VERSION 5.7 ;
  NOWIREEXTENSIONATPIN ON ;
  DIVIDERCHAR "/" ;
  BUSBITCHARS "[]" ;
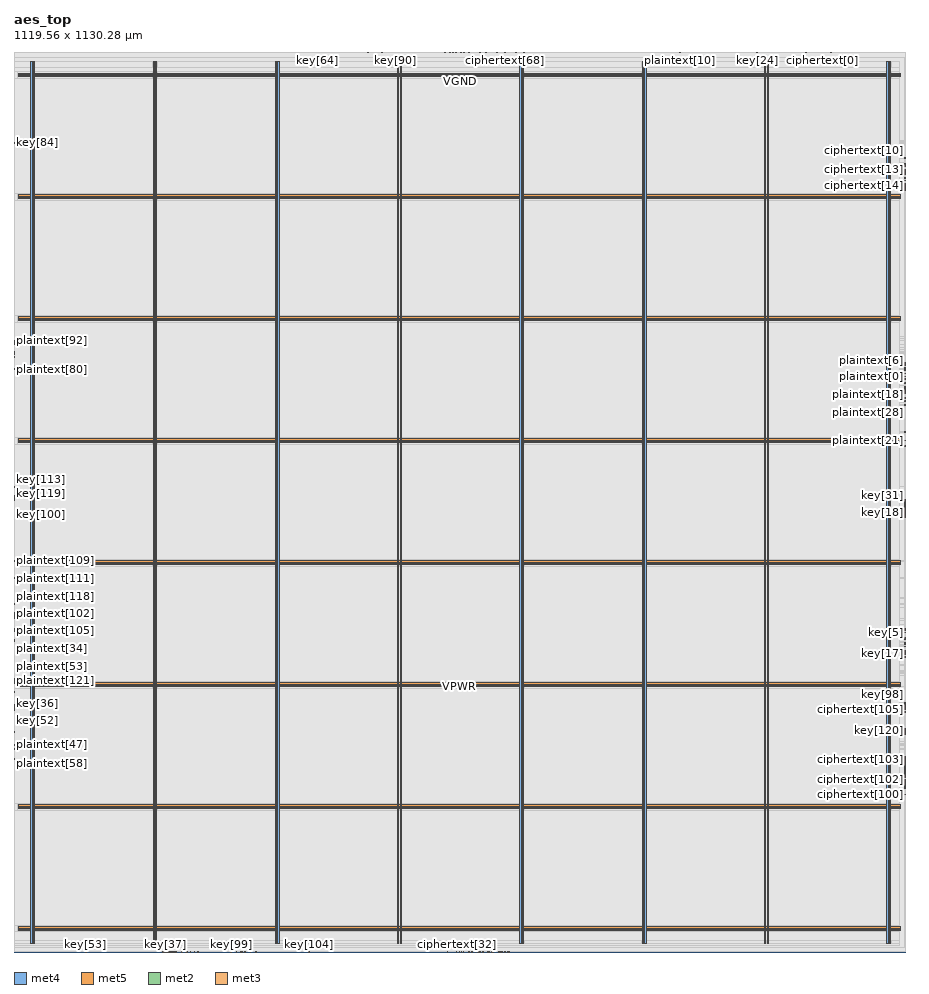
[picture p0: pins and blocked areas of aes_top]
MACRO aes_top
  CLASS BLOCK ;
  FOREIGN aes_top ;
  ORIGIN 0.000 0.000 ;
  SIZE 1119.560 BY 1130.280 ;
  PIN VGND
    DIRECTION INOUT ;
    USE GROUND ;
    PORT
      LAYER met4 ;
        RECT 24.340 10.640 25.940 1118.160 ;
    END
    PORT
      LAYER met4 ;
        RECT 177.940 10.640 179.540 1118.160 ;
    END
    PORT
      LAYER met4 ;
        RECT 331.540 10.640 333.140 1118.160 ;
    END
    PORT
      LAYER met4 ;
        RECT 485.140 10.640 486.740 1118.160 ;
    END
    PORT
      LAYER met4 ;
        RECT 638.740 10.640 640.340 1118.160 ;
    END
    PORT
      LAYER met4 ;
        RECT 792.340 10.640 793.940 1118.160 ;
    END
    PORT
      LAYER met4 ;
        RECT 945.940 10.640 947.540 1118.160 ;
    END
    PORT
      LAYER met4 ;
        RECT 1099.540 10.640 1101.140 1118.160 ;
    END
    PORT
      LAYER met5 ;
        RECT 5.520 30.030 1113.660 31.630 ;
    END
    PORT
      LAYER met5 ;
        RECT 5.520 183.210 1113.660 184.810 ;
    END
    PORT
      LAYER met5 ;
        RECT 5.520 336.390 1113.660 337.990 ;
    END
    PORT
      LAYER met5 ;
        RECT 5.520 489.570 1113.660 491.170 ;
    END
    PORT
      LAYER met5 ;
        RECT 5.520 642.750 1113.660 644.350 ;
    END
    PORT
      LAYER met5 ;
        RECT 5.520 795.930 1113.660 797.530 ;
    END
    PORT
      LAYER met5 ;
        RECT 5.520 949.110 1113.660 950.710 ;
    END
    PORT
      LAYER met5 ;
        RECT 5.520 1102.290 1113.660 1103.890 ;
    END
  END VGND
  PIN VPWR
    DIRECTION INOUT ;
    USE POWER ;
    PORT
      LAYER met4 ;
        RECT 21.040 10.640 22.640 1118.160 ;
    END
    PORT
      LAYER met4 ;
        RECT 174.640 10.640 176.240 1118.160 ;
    END
    PORT
      LAYER met4 ;
        RECT 328.240 10.640 329.840 1118.160 ;
    END
    PORT
      LAYER met4 ;
        RECT 481.840 10.640 483.440 1118.160 ;
    END
    PORT
      LAYER met4 ;
        RECT 635.440 10.640 637.040 1118.160 ;
    END
    PORT
      LAYER met4 ;
        RECT 789.040 10.640 790.640 1118.160 ;
    END
    PORT
      LAYER met4 ;
        RECT 942.640 10.640 944.240 1118.160 ;
    END
    PORT
      LAYER met4 ;
        RECT 1096.240 10.640 1097.840 1118.160 ;
    END
    PORT
      LAYER met5 ;
        RECT 5.520 26.730 1113.660 28.330 ;
    END
    PORT
      LAYER met5 ;
        RECT 5.520 179.910 1113.660 181.510 ;
    END
    PORT
      LAYER met5 ;
        RECT 5.520 333.090 1113.660 334.690 ;
    END
    PORT
      LAYER met5 ;
        RECT 5.520 486.270 1113.660 487.870 ;
    END
    PORT
      LAYER met5 ;
        RECT 5.520 639.450 1113.660 641.050 ;
    END
    PORT
      LAYER met5 ;
        RECT 5.520 792.630 1113.660 794.230 ;
    END
    PORT
      LAYER met5 ;
        RECT 5.520 945.810 1113.660 947.410 ;
    END
    PORT
      LAYER met5 ;
        RECT 5.520 1098.990 1113.660 1100.590 ;
    END
  END VPWR
  PIN ciphertext[0]
    DIRECTION OUTPUT ;
    USE SIGNAL ;
    ANTENNAGATEAREA 0.126000 ;
    ANTENNADIFFAREA 0.429000 ;
    PORT
      LAYER met2 ;
        RECT 1014.850 1130.000 1015.130 1130.280 ;
    END
  END ciphertext[0]
  PIN ciphertext[100]
    DIRECTION OUTPUT ;
    USE SIGNAL ;
    ANTENNAGATEAREA 0.126000 ;
    ANTENNADIFFAREA 0.429000 ;
    PORT
      LAYER met3 ;
        RECT 1118.960 197.240 1119.560 197.840 ;
    END
  END ciphertext[100]
  PIN ciphertext[101]
    DIRECTION OUTPUT ;
    USE SIGNAL ;
    ANTENNADIFFAREA 0.445500 ;
    PORT
      LAYER met3 ;
        RECT 1118.960 212.200 1119.560 212.800 ;
    END
  END ciphertext[101]
  PIN ciphertext[102]
    DIRECTION OUTPUT ;
    USE SIGNAL ;
    ANTENNADIFFAREA 0.383400 ;
    PORT
      LAYER met3 ;
        RECT 1118.960 216.280 1119.560 216.880 ;
    END
  END ciphertext[102]
  PIN ciphertext[103]
    DIRECTION OUTPUT ;
    USE SIGNAL ;
    ANTENNAGATEAREA 0.126000 ;
    ANTENNADIFFAREA 0.429000 ;
    PORT
      LAYER met3 ;
        RECT 1118.960 231.240 1119.560 231.840 ;
    END
  END ciphertext[103]
  PIN ciphertext[104]
    DIRECTION OUTPUT ;
    USE SIGNAL ;
    ANTENNAGATEAREA 0.126000 ;
    ANTENNADIFFAREA 0.429000 ;
    PORT
      LAYER met3 ;
        RECT 1118.960 221.720 1119.560 222.320 ;
    END
  END ciphertext[104]
  PIN ciphertext[105]
    DIRECTION OUTPUT ;
    USE SIGNAL ;
    ANTENNAGATEAREA 0.126000 ;
    ANTENNADIFFAREA 0.429000 ;
    PORT
      LAYER met3 ;
        RECT 1118.960 304.680 1119.560 305.280 ;
    END
  END ciphertext[105]
  PIN ciphertext[106]
    DIRECTION OUTPUT ;
    USE SIGNAL ;
    ANTENNAGATEAREA 0.126000 ;
    ANTENNADIFFAREA 0.429000 ;
    PORT
      LAYER met3 ;
        RECT 1118.960 306.040 1119.560 306.640 ;
    END
  END ciphertext[106]
  PIN ciphertext[107]
    DIRECTION OUTPUT ;
    USE SIGNAL ;
    ANTENNAGATEAREA 0.126000 ;
    ANTENNADIFFAREA 0.429000 ;
    PORT
      LAYER met3 ;
        RECT 1118.960 239.400 1119.560 240.000 ;
    END
  END ciphertext[107]
  PIN ciphertext[108]
    DIRECTION OUTPUT ;
    USE SIGNAL ;
    ANTENNAGATEAREA 0.126000 ;
    ANTENNADIFFAREA 0.429000 ;
    PORT
      LAYER met3 ;
        RECT 1118.960 213.560 1119.560 214.160 ;
    END
  END ciphertext[108]
  PIN ciphertext[109]
    DIRECTION OUTPUT ;
    USE SIGNAL ;
    ANTENNAGATEAREA 0.126000 ;
    ANTENNADIFFAREA 0.429000 ;
    PORT
      LAYER met3 ;
        RECT 1118.960 208.120 1119.560 208.720 ;
    END
  END ciphertext[109]
  PIN ciphertext[10]
    DIRECTION OUTPUT ;
    USE SIGNAL ;
    ANTENNAGATEAREA 0.126000 ;
    ANTENNADIFFAREA 0.429000 ;
    PORT
      LAYER met3 ;
        RECT 1118.960 996.920 1119.560 997.520 ;
    END
  END ciphertext[10]
  PIN ciphertext[110]
    DIRECTION OUTPUT ;
    USE SIGNAL ;
    ANTENNAGATEAREA 0.126000 ;
    ANTENNADIFFAREA 0.429000 ;
    PORT
      LAYER met3 ;
        RECT 1118.960 210.840 1119.560 211.440 ;
    END
  END ciphertext[110]
  PIN ciphertext[111]
    DIRECTION OUTPUT ;
    USE SIGNAL ;
    ANTENNAGATEAREA 0.126000 ;
    ANTENNADIFFAREA 0.429000 ;
    PORT
      LAYER met3 ;
        RECT 1118.960 242.120 1119.560 242.720 ;
    END
  END ciphertext[111]
  PIN ciphertext[112]
    DIRECTION OUTPUT ;
    USE SIGNAL ;
    ANTENNADIFFAREA 0.702900 ;
    PORT
      LAYER met3 ;
        RECT 1118.960 238.040 1119.560 238.640 ;
    END
  END ciphertext[112]
  PIN ciphertext[113]
    DIRECTION OUTPUT ;
    USE SIGNAL ;
    ANTENNAGATEAREA 0.126000 ;
    ANTENNADIFFAREA 0.429000 ;
    PORT
      LAYER met3 ;
        RECT 1118.960 301.960 1119.560 302.560 ;
    END
  END ciphertext[113]
  PIN ciphertext[114]
    DIRECTION OUTPUT ;
    USE SIGNAL ;
    ANTENNADIFFAREA 0.702900 ;
    PORT
      LAYER met3 ;
        RECT 1118.960 300.600 1119.560 301.200 ;
    END
  END ciphertext[114]
  PIN ciphertext[115]
    DIRECTION OUTPUT ;
    USE SIGNAL ;
    ANTENNADIFFAREA 0.702900 ;
    PORT
      LAYER met3 ;
        RECT 1118.960 236.680 1119.560 237.280 ;
    END
  END ciphertext[115]
  PIN ciphertext[116]
    DIRECTION OUTPUT ;
    USE SIGNAL ;
    ANTENNAGATEAREA 0.126000 ;
    ANTENNADIFFAREA 0.429000 ;
    PORT
      LAYER met3 ;
        RECT 1118.960 214.920 1119.560 215.520 ;
    END
  END ciphertext[116]
  PIN ciphertext[117]
    DIRECTION OUTPUT ;
    USE SIGNAL ;
    ANTENNAGATEAREA 0.126000 ;
    ANTENNADIFFAREA 0.429000 ;
    PORT
      LAYER met3 ;
        RECT 1118.960 206.760 1119.560 207.360 ;
    END
  END ciphertext[117]
  PIN ciphertext[118]
    DIRECTION OUTPUT ;
    USE SIGNAL ;
    ANTENNAGATEAREA 0.126000 ;
    ANTENNADIFFAREA 0.429000 ;
    PORT
      LAYER met3 ;
        RECT 1118.960 219.000 1119.560 219.600 ;
    END
  END ciphertext[118]
  PIN ciphertext[119]
    DIRECTION OUTPUT ;
    USE SIGNAL ;
    ANTENNADIFFAREA 0.702900 ;
    PORT
      LAYER met3 ;
        RECT 1118.960 235.320 1119.560 235.920 ;
    END
  END ciphertext[119]
  PIN ciphertext[11]
    DIRECTION OUTPUT ;
    USE SIGNAL ;
    ANTENNADIFFAREA 0.383400 ;
    PORT
      LAYER met3 ;
        RECT 1118.960 976.520 1119.560 977.120 ;
    END
  END ciphertext[11]
  PIN ciphertext[120]
    DIRECTION OUTPUT ;
    USE SIGNAL ;
    ANTENNAGATEAREA 0.126000 ;
    ANTENNADIFFAREA 0.429000 ;
    PORT
      LAYER met3 ;
        RECT 1118.960 232.600 1119.560 233.200 ;
    END
  END ciphertext[120]
  PIN ciphertext[121]
    DIRECTION OUTPUT ;
    USE SIGNAL ;
    ANTENNADIFFAREA 0.445500 ;
    PORT
      LAYER met3 ;
        RECT 1118.960 311.480 1119.560 312.080 ;
    END
  END ciphertext[121]
  PIN ciphertext[122]
    DIRECTION OUTPUT ;
    USE SIGNAL ;
    ANTENNADIFFAREA 0.702900 ;
    PORT
      LAYER met3 ;
        RECT 1118.960 310.120 1119.560 310.720 ;
    END
  END ciphertext[122]
  PIN ciphertext[123]
    DIRECTION OUTPUT ;
    USE SIGNAL ;
    ANTENNAGATEAREA 0.126000 ;
    ANTENNADIFFAREA 0.429000 ;
    PORT
      LAYER met3 ;
        RECT 1118.960 244.840 1119.560 245.440 ;
    END
  END ciphertext[123]
  PIN ciphertext[124]
    DIRECTION OUTPUT ;
    USE SIGNAL ;
    ANTENNADIFFAREA 0.383400 ;
    PORT
      LAYER met3 ;
        RECT 1118.960 205.400 1119.560 206.000 ;
    END
  END ciphertext[124]
  PIN ciphertext[125]
    DIRECTION OUTPUT ;
    USE SIGNAL ;
    ANTENNADIFFAREA 0.702900 ;
    PORT
      LAYER met3 ;
        RECT 1118.960 209.480 1119.560 210.080 ;
    END
  END ciphertext[125]
  PIN ciphertext[126]
    DIRECTION OUTPUT ;
    USE SIGNAL ;
    ANTENNAGATEAREA 0.126000 ;
    ANTENNADIFFAREA 0.429000 ;
    PORT
      LAYER met3 ;
        RECT 1118.960 220.360 1119.560 220.960 ;
    END
  END ciphertext[126]
  PIN ciphertext[127]
    DIRECTION OUTPUT ;
    USE SIGNAL ;
    ANTENNAGATEAREA 0.126000 ;
    ANTENNADIFFAREA 0.429000 ;
    PORT
      LAYER met3 ;
        RECT 1118.960 227.160 1119.560 227.760 ;
    END
  END ciphertext[127]
  PIN ciphertext[12]
    DIRECTION OUTPUT ;
    USE SIGNAL ;
    ANTENNAGATEAREA 0.126000 ;
    ANTENNADIFFAREA 0.429000 ;
    PORT
      LAYER met3 ;
        RECT 1118.960 956.120 1119.560 956.720 ;
    END
  END ciphertext[12]
  PIN ciphertext[13]
    DIRECTION OUTPUT ;
    USE SIGNAL ;
    ANTENNADIFFAREA 0.702900 ;
    PORT
      LAYER met3 ;
        RECT 1118.960 981.960 1119.560 982.560 ;
    END
  END ciphertext[13]
  PIN ciphertext[14]
    DIRECTION OUTPUT ;
    USE SIGNAL ;
    ANTENNADIFFAREA 0.383400 ;
    PORT
      LAYER met3 ;
        RECT 1118.960 972.440 1119.560 973.040 ;
    END
  END ciphertext[14]
  PIN ciphertext[15]
    DIRECTION OUTPUT ;
    USE SIGNAL ;
    ANTENNAGATEAREA 0.126000 ;
    ANTENNADIFFAREA 0.429000 ;
    PORT
      LAYER met3 ;
        RECT 1118.960 990.120 1119.560 990.720 ;
    END
  END ciphertext[15]
  PIN ciphertext[16]
    DIRECTION OUTPUT ;
    USE SIGNAL ;
    ANTENNAGATEAREA 0.126000 ;
    ANTENNADIFFAREA 0.429000 ;
    PORT
      LAYER met2 ;
        RECT 995.530 1130.000 995.810 1130.280 ;
    END
  END ciphertext[16]
  PIN ciphertext[17]
    DIRECTION OUTPUT ;
    USE SIGNAL ;
    ANTENNAGATEAREA 0.126000 ;
    ANTENNADIFFAREA 0.429000 ;
    PORT
      LAYER met2 ;
        RECT 1018.530 1130.000 1018.810 1130.280 ;
    END
  END ciphertext[17]
  PIN ciphertext[18]
    DIRECTION OUTPUT ;
    USE SIGNAL ;
    ANTENNADIFFAREA 0.383400 ;
    PORT
      LAYER met2 ;
        RECT 1031.410 1130.000 1031.690 1130.280 ;
    END
  END ciphertext[18]
  PIN ciphertext[19]
    DIRECTION OUTPUT ;
    USE SIGNAL ;
    ANTENNADIFFAREA 0.445500 ;
    PORT
      LAYER met3 ;
        RECT 1118.960 958.840 1119.560 959.440 ;
    END
  END ciphertext[19]
  PIN ciphertext[1]
    DIRECTION OUTPUT ;
    USE SIGNAL ;
    ANTENNADIFFAREA 0.795200 ;
    PORT
      LAYER met2 ;
        RECT 1019.450 1130.000 1019.730 1130.280 ;
    END
  END ciphertext[1]
  PIN ciphertext[20]
    DIRECTION OUTPUT ;
    USE SIGNAL ;
    ANTENNADIFFAREA 0.445500 ;
    PORT
      LAYER met3 ;
        RECT 1118.960 957.480 1119.560 958.080 ;
    END
  END ciphertext[20]
  PIN ciphertext[21]
    DIRECTION OUTPUT ;
    USE SIGNAL ;
    ANTENNAGATEAREA 0.126000 ;
    ANTENNADIFFAREA 0.429000 ;
    PORT
      LAYER met3 ;
        RECT 1118.960 977.880 1119.560 978.480 ;
    END
  END ciphertext[21]
  PIN ciphertext[22]
    DIRECTION OUTPUT ;
    USE SIGNAL ;
    ANTENNAGATEAREA 0.126000 ;
    ANTENNADIFFAREA 0.429000 ;
    PORT
      LAYER met2 ;
        RECT 990.930 1130.000 991.210 1130.280 ;
    END
  END ciphertext[22]
  PIN ciphertext[23]
    DIRECTION OUTPUT ;
    USE SIGNAL ;
    ANTENNAGATEAREA 0.126000 ;
    ANTENNADIFFAREA 0.429000 ;
    PORT
      LAYER met3 ;
        RECT 1118.960 986.040 1119.560 986.640 ;
    END
  END ciphertext[23]
  PIN ciphertext[24]
    DIRECTION OUTPUT ;
    USE SIGNAL ;
    ANTENNAGATEAREA 0.126000 ;
    ANTENNADIFFAREA 0.429000 ;
    PORT
      LAYER met2 ;
        RECT 999.210 1130.000 999.490 1130.280 ;
    END
  END ciphertext[24]
  PIN ciphertext[25]
    DIRECTION OUTPUT ;
    USE SIGNAL ;
    ANTENNAGATEAREA 0.126000 ;
    ANTENNADIFFAREA 0.429000 ;
    PORT
      LAYER met2 ;
        RECT 1013.930 1130.000 1014.210 1130.280 ;
    END
  END ciphertext[25]
  PIN ciphertext[26]
    DIRECTION OUTPUT ;
    USE SIGNAL ;
    ANTENNAGATEAREA 0.126000 ;
    ANTENNADIFFAREA 0.429000 ;
    PORT
      LAYER met2 ;
        RECT 1026.810 1130.000 1027.090 1130.280 ;
    END
  END ciphertext[26]
  PIN ciphertext[27]
    DIRECTION OUTPUT ;
    USE SIGNAL ;
    ANTENNADIFFAREA 0.445500 ;
    PORT
      LAYER met3 ;
        RECT 1118.960 960.200 1119.560 960.800 ;
    END
  END ciphertext[27]
  PIN ciphertext[28]
    DIRECTION OUTPUT ;
    USE SIGNAL ;
    ANTENNADIFFAREA 0.445500 ;
    PORT
      LAYER met3 ;
        RECT 1118.960 961.560 1119.560 962.160 ;
    END
  END ciphertext[28]
  PIN ciphertext[29]
    DIRECTION OUTPUT ;
    USE SIGNAL ;
    ANTENNAGATEAREA 0.126000 ;
    ANTENNADIFFAREA 0.429000 ;
    PORT
      LAYER met3 ;
        RECT 1118.960 971.080 1119.560 971.680 ;
    END
  END ciphertext[29]
  PIN ciphertext[2]
    DIRECTION OUTPUT ;
    USE SIGNAL ;
    ANTENNAGATEAREA 0.126000 ;
    ANTENNADIFFAREA 0.429000 ;
    PORT
      LAYER met2 ;
        RECT 1025.890 1130.000 1026.170 1130.280 ;
    END
  END ciphertext[2]
  PIN ciphertext[30]
    DIRECTION OUTPUT ;
    USE SIGNAL ;
    ANTENNAGATEAREA 0.126000 ;
    ANTENNADIFFAREA 0.429000 ;
    PORT
      LAYER met3 ;
        RECT 1118.960 987.400 1119.560 988.000 ;
    END
  END ciphertext[30]
  PIN ciphertext[31]
    DIRECTION OUTPUT ;
    USE SIGNAL ;
    ANTENNADIFFAREA 0.383400 ;
    PORT
      LAYER met2 ;
        RECT 1001.050 1130.000 1001.330 1130.280 ;
    END
  END ciphertext[31]
  PIN ciphertext[32]
    DIRECTION OUTPUT ;
    USE SIGNAL ;
    ANTENNAGATEAREA 0.126000 ;
    ANTENNADIFFAREA 0.429000 ;
    PORT
      LAYER met2 ;
        RECT 555.770 0.000 556.050 0.280 ;
    END
  END ciphertext[32]
  PIN ciphertext[33]
    DIRECTION OUTPUT ;
    USE SIGNAL ;
    ANTENNAGATEAREA 0.126000 ;
    ANTENNADIFFAREA 0.429000 ;
    PORT
      LAYER met2 ;
        RECT 571.410 0.000 571.690 0.280 ;
    END
  END ciphertext[33]
  PIN ciphertext[34]
    DIRECTION OUTPUT ;
    USE SIGNAL ;
    ANTENNADIFFAREA 0.383400 ;
    PORT
      LAYER met2 ;
        RECT 599.930 0.000 600.210 0.280 ;
    END
  END ciphertext[34]
  PIN ciphertext[35]
    DIRECTION OUTPUT ;
    USE SIGNAL ;
    ANTENNADIFFAREA 0.383400 ;
    PORT
      LAYER met2 ;
        RECT 620.170 0.000 620.450 0.280 ;
    END
  END ciphertext[35]
  PIN ciphertext[36]
    DIRECTION OUTPUT ;
    USE SIGNAL ;
    ANTENNAGATEAREA 0.126000 ;
    ANTENNADIFFAREA 0.429000 ;
    PORT
      LAYER met2 ;
        RECT 608.210 0.000 608.490 0.280 ;
    END
  END ciphertext[36]
  PIN ciphertext[37]
    DIRECTION OUTPUT ;
    USE SIGNAL ;
    ANTENNAGATEAREA 0.126000 ;
    ANTENNADIFFAREA 0.429000 ;
    PORT
      LAYER met2 ;
        RECT 612.810 0.000 613.090 0.280 ;
    END
  END ciphertext[37]
  PIN ciphertext[38]
    DIRECTION OUTPUT ;
    USE SIGNAL ;
    ANTENNAGATEAREA 0.126000 ;
    ANTENNADIFFAREA 0.429000 ;
    PORT
      LAYER met2 ;
        RECT 582.450 0.000 582.730 0.280 ;
    END
  END ciphertext[38]
  PIN ciphertext[39]
    DIRECTION OUTPUT ;
    USE SIGNAL ;
    ANTENNAGATEAREA 0.126000 ;
    ANTENNADIFFAREA 0.429000 ;
    PORT
      LAYER met2 ;
        RECT 575.090 0.000 575.370 0.280 ;
    END
  END ciphertext[39]
  PIN ciphertext[3]
    DIRECTION OUTPUT ;
    USE SIGNAL ;
    ANTENNADIFFAREA 0.383400 ;
    PORT
      LAYER met3 ;
        RECT 1118.960 968.360 1119.560 968.960 ;
    END
  END ciphertext[3]
  PIN ciphertext[40]
    DIRECTION OUTPUT ;
    USE SIGNAL ;
    ANTENNADIFFAREA 0.702900 ;
    PORT
      LAYER met2 ;
        RECT 564.050 0.000 564.330 0.280 ;
    END
  END ciphertext[40]
  PIN ciphertext[41]
    DIRECTION OUTPUT ;
    USE SIGNAL ;
    ANTENNADIFFAREA 0.383400 ;
    PORT
      LAYER met2 ;
        RECT 559.450 0.000 559.730 0.280 ;
    END
  END ciphertext[41]
  PIN ciphertext[42]
    DIRECTION OUTPUT ;
    USE SIGNAL ;
    ANTENNADIFFAREA 0.383400 ;
    PORT
      LAYER met2 ;
        RECT 600.850 0.000 601.130 0.280 ;
    END
  END ciphertext[42]
  PIN ciphertext[43]
    DIRECTION OUTPUT ;
    USE SIGNAL ;
    ANTENNAGATEAREA 0.126000 ;
    ANTENNADIFFAREA 0.429000 ;
    PORT
      LAYER met2 ;
        RECT 610.050 0.000 610.330 0.280 ;
    END
  END ciphertext[43]
  PIN ciphertext[44]
    DIRECTION OUTPUT ;
    USE SIGNAL ;
    ANTENNAGATEAREA 0.126000 ;
    ANTENNADIFFAREA 0.429000 ;
    PORT
      LAYER met2 ;
        RECT 610.970 0.000 611.250 0.280 ;
    END
  END ciphertext[44]
  PIN ciphertext[45]
    DIRECTION OUTPUT ;
    USE SIGNAL ;
    ANTENNAGATEAREA 0.126000 ;
    ANTENNADIFFAREA 0.429000 ;
    PORT
      LAYER met2 ;
        RECT 609.130 0.000 609.410 0.280 ;
    END
  END ciphertext[45]
  PIN ciphertext[46]
    DIRECTION OUTPUT ;
    USE SIGNAL ;
    ANTENNAGATEAREA 0.126000 ;
    ANTENNADIFFAREA 0.429000 ;
    PORT
      LAYER met2 ;
        RECT 594.410 0.000 594.690 0.280 ;
    END
  END ciphertext[46]
  PIN ciphertext[47]
    DIRECTION OUTPUT ;
    USE SIGNAL ;
    ANTENNADIFFAREA 0.702900 ;
    PORT
      LAYER met2 ;
        RECT 576.010 0.000 576.290 0.280 ;
    END
  END ciphertext[47]
  PIN ciphertext[48]
    DIRECTION OUTPUT ;
    USE SIGNAL ;
    ANTENNAGATEAREA 0.126000 ;
    ANTENNADIFFAREA 0.429000 ;
    PORT
      LAYER met2 ;
        RECT 543.810 0.000 544.090 0.280 ;
    END
  END ciphertext[48]
  PIN ciphertext[49]
    DIRECTION OUTPUT ;
    USE SIGNAL ;
    ANTENNADIFFAREA 0.383400 ;
    PORT
      LAYER met2 ;
        RECT 562.210 0.000 562.490 0.280 ;
    END
  END ciphertext[49]
  PIN ciphertext[4]
    DIRECTION OUTPUT ;
    USE SIGNAL ;
    ANTENNAGATEAREA 0.126000 ;
    ANTENNADIFFAREA 0.429000 ;
    PORT
      LAYER met3 ;
        RECT 1118.960 964.280 1119.560 964.880 ;
    END
  END ciphertext[4]
  PIN ciphertext[50]
    DIRECTION OUTPUT ;
    USE SIGNAL ;
    ANTENNAGATEAREA 0.126000 ;
    ANTENNADIFFAREA 0.429000 ;
    PORT
      LAYER met2 ;
        RECT 597.170 0.000 597.450 0.280 ;
    END
  END ciphertext[50]
  PIN ciphertext[51]
    DIRECTION OUTPUT ;
    USE SIGNAL ;
    ANTENNAGATEAREA 0.126000 ;
    ANTENNADIFFAREA 0.429000 ;
    PORT
      LAYER met2 ;
        RECT 617.410 0.000 617.690 0.280 ;
    END
  END ciphertext[51]
  PIN ciphertext[52]
    DIRECTION OUTPUT ;
    USE SIGNAL ;
    ANTENNAGATEAREA 0.126000 ;
    ANTENNADIFFAREA 0.429000 ;
    PORT
      LAYER met2 ;
        RECT 616.490 0.000 616.770 0.280 ;
    END
  END ciphertext[52]
  PIN ciphertext[53]
    DIRECTION OUTPUT ;
    USE SIGNAL ;
    ANTENNAGATEAREA 0.126000 ;
    ANTENNADIFFAREA 0.429000 ;
    PORT
      LAYER met2 ;
        RECT 596.250 0.000 596.530 0.280 ;
    END
  END ciphertext[53]
  PIN ciphertext[54]
    DIRECTION OUTPUT ;
    USE SIGNAL ;
    ANTENNAGATEAREA 0.126000 ;
    ANTENNADIFFAREA 0.429000 ;
    PORT
      LAYER met2 ;
        RECT 595.330 0.000 595.610 0.280 ;
    END
  END ciphertext[54]
  PIN ciphertext[55]
    DIRECTION OUTPUT ;
    USE SIGNAL ;
    ANTENNAGATEAREA 0.126000 ;
    ANTENNADIFFAREA 0.429000 ;
    PORT
      LAYER met2 ;
        RECT 584.290 0.000 584.570 0.280 ;
    END
  END ciphertext[55]
  PIN ciphertext[56]
    DIRECTION OUTPUT ;
    USE SIGNAL ;
    ANTENNAGATEAREA 0.126000 ;
    ANTENNADIFFAREA 0.429000 ;
    PORT
      LAYER met2 ;
        RECT 579.690 0.000 579.970 0.280 ;
    END
  END ciphertext[56]
  PIN ciphertext[57]
    DIRECTION OUTPUT ;
    USE SIGNAL ;
    ANTENNAGATEAREA 0.126000 ;
    ANTENNADIFFAREA 0.429000 ;
    PORT
      LAYER met2 ;
        RECT 587.970 0.000 588.250 0.280 ;
    END
  END ciphertext[57]
  PIN ciphertext[58]
    DIRECTION OUTPUT ;
    USE SIGNAL ;
    ANTENNADIFFAREA 0.702900 ;
    PORT
      LAYER met2 ;
        RECT 572.330 0.000 572.610 0.280 ;
    END
  END ciphertext[58]
  PIN ciphertext[59]
    DIRECTION OUTPUT ;
    USE SIGNAL ;
    ANTENNADIFFAREA 0.383400 ;
    PORT
      LAYER met2 ;
        RECT 622.010 0.000 622.290 0.280 ;
    END
  END ciphertext[59]
  PIN ciphertext[5]
    DIRECTION OUTPUT ;
    USE SIGNAL ;
    ANTENNADIFFAREA 0.702900 ;
    PORT
      LAYER met3 ;
        RECT 1118.960 988.760 1119.560 989.360 ;
    END
  END ciphertext[5]
  PIN ciphertext[60]
    DIRECTION OUTPUT ;
    USE SIGNAL ;
    ANTENNAGATEAREA 0.126000 ;
    ANTENNADIFFAREA 0.429000 ;
    PORT
      LAYER met2 ;
        RECT 615.570 0.000 615.850 0.280 ;
    END
  END ciphertext[60]
  PIN ciphertext[61]
    DIRECTION OUTPUT ;
    USE SIGNAL ;
    ANTENNAGATEAREA 0.126000 ;
    ANTENNADIFFAREA 0.429000 ;
    PORT
      LAYER met2 ;
        RECT 601.770 0.000 602.050 0.280 ;
    END
  END ciphertext[61]
  PIN ciphertext[62]
    DIRECTION OUTPUT ;
    USE SIGNAL ;
    ANTENNADIFFAREA 0.383400 ;
    PORT
      LAYER met2 ;
        RECT 588.890 0.000 589.170 0.280 ;
    END
  END ciphertext[62]
  PIN ciphertext[63]
    DIRECTION OUTPUT ;
    USE SIGNAL ;
    ANTENNADIFFAREA 0.383400 ;
    PORT
      LAYER met2 ;
        RECT 585.210 0.000 585.490 0.280 ;
    END
  END ciphertext[63]
  PIN ciphertext[64]
    DIRECTION OUTPUT ;
    USE SIGNAL ;
    ANTENNADIFFAREA 0.702900 ;
    PORT
      LAYER met2 ;
        RECT 571.410 1130.000 571.690 1130.280 ;
    END
  END ciphertext[64]
  PIN ciphertext[65]
    DIRECTION OUTPUT ;
    USE SIGNAL ;
    ANTENNAGATEAREA 0.126000 ;
    ANTENNADIFFAREA 0.429000 ;
    PORT
      LAYER met2 ;
        RECT 607.290 1130.000 607.570 1130.280 ;
    END
  END ciphertext[65]
  PIN ciphertext[66]
    DIRECTION OUTPUT ;
    USE SIGNAL ;
    ANTENNAGATEAREA 0.126000 ;
    ANTENNADIFFAREA 0.429000 ;
    PORT
      LAYER met2 ;
        RECT 653.290 1130.000 653.570 1130.280 ;
    END
  END ciphertext[66]
  PIN ciphertext[67]
    DIRECTION OUTPUT ;
    USE SIGNAL ;
    ANTENNAGATEAREA 0.126000 ;
    ANTENNADIFFAREA 0.429000 ;
    PORT
      LAYER met2 ;
        RECT 640.410 1130.000 640.690 1130.280 ;
    END
  END ciphertext[67]
  PIN ciphertext[68]
    DIRECTION OUTPUT ;
    USE SIGNAL ;
    ANTENNAGATEAREA 0.126000 ;
    ANTENNADIFFAREA 0.429000 ;
    PORT
      LAYER met2 ;
        RECT 616.490 1130.000 616.770 1130.280 ;
    END
  END ciphertext[68]
  PIN ciphertext[69]
    DIRECTION OUTPUT ;
    USE SIGNAL ;
    ANTENNAGATEAREA 0.126000 ;
    ANTENNADIFFAREA 0.429000 ;
    PORT
      LAYER met2 ;
        RECT 609.130 1130.000 609.410 1130.280 ;
    END
  END ciphertext[69]
  PIN ciphertext[6]
    DIRECTION OUTPUT ;
    USE SIGNAL ;
    ANTENNADIFFAREA 0.383400 ;
    PORT
      LAYER met3 ;
        RECT 1118.960 979.240 1119.560 979.840 ;
    END
  END ciphertext[6]
  PIN ciphertext[70]
    DIRECTION OUTPUT ;
    USE SIGNAL ;
    ANTENNAGATEAREA 0.126000 ;
    ANTENNADIFFAREA 0.429000 ;
    PORT
      LAYER met2 ;
        RECT 592.570 1130.000 592.850 1130.280 ;
    END
  END ciphertext[70]
  PIN ciphertext[71]
    DIRECTION OUTPUT ;
    USE SIGNAL ;
    ANTENNADIFFAREA 0.702900 ;
    PORT
      LAYER met2 ;
        RECT 580.610 1130.000 580.890 1130.280 ;
    END
  END ciphertext[71]
  PIN ciphertext[72]
    DIRECTION OUTPUT ;
    USE SIGNAL ;
    ANTENNAGATEAREA 0.126000 ;
    ANTENNADIFFAREA 0.429000 ;
    PORT
      LAYER met2 ;
        RECT 584.290 1130.000 584.570 1130.280 ;
    END
  END ciphertext[72]
  PIN ciphertext[73]
    DIRECTION OUTPUT ;
    USE SIGNAL ;
    ANTENNADIFFAREA 0.383400 ;
    PORT
      LAYER met2 ;
        RECT 619.250 1130.000 619.530 1130.280 ;
    END
  END ciphertext[73]
  PIN ciphertext[74]
    DIRECTION OUTPUT ;
    USE SIGNAL ;
    ANTENNADIFFAREA 0.702900 ;
    PORT
      LAYER met2 ;
        RECT 642.250 1130.000 642.530 1130.280 ;
    END
  END ciphertext[74]
  PIN ciphertext[75]
    DIRECTION OUTPUT ;
    USE SIGNAL ;
    ANTENNAGATEAREA 0.126000 ;
    ANTENNADIFFAREA 0.429000 ;
    PORT
      LAYER met2 ;
        RECT 639.490 1130.000 639.770 1130.280 ;
    END
  END ciphertext[75]
  PIN ciphertext[76]
    DIRECTION OUTPUT ;
    USE SIGNAL ;
    ANTENNAGATEAREA 0.126000 ;
    ANTENNADIFFAREA 0.429000 ;
    PORT
      LAYER met2 ;
        RECT 608.210 1130.000 608.490 1130.280 ;
    END
  END ciphertext[76]
  PIN ciphertext[77]
    DIRECTION OUTPUT ;
    USE SIGNAL ;
    ANTENNAGATEAREA 0.126000 ;
    ANTENNADIFFAREA 0.429000 ;
    PORT
      LAYER met2 ;
        RECT 605.450 1130.000 605.730 1130.280 ;
    END
  END ciphertext[77]
  PIN ciphertext[78]
    DIRECTION OUTPUT ;
    USE SIGNAL ;
    ANTENNAGATEAREA 0.126000 ;
    ANTENNADIFFAREA 0.429000 ;
    PORT
      LAYER met2 ;
        RECT 595.330 1130.000 595.610 1130.280 ;
    END
  END ciphertext[78]
  PIN ciphertext[79]
    DIRECTION OUTPUT ;
    USE SIGNAL ;
    ANTENNADIFFAREA 0.702900 ;
    PORT
      LAYER met2 ;
        RECT 581.530 1130.000 581.810 1130.280 ;
    END
  END ciphertext[79]
  PIN ciphertext[7]
    DIRECTION OUTPUT ;
    USE SIGNAL ;
    ANTENNAGATEAREA 0.126000 ;
    ANTENNADIFFAREA 0.429000 ;
    PORT
      LAYER met2 ;
        RECT 1016.690 1130.000 1016.970 1130.280 ;
    END
  END ciphertext[7]
  PIN ciphertext[80]
    DIRECTION OUTPUT ;
    USE SIGNAL ;
    ANTENNADIFFAREA 0.383400 ;
    PORT
      LAYER met2 ;
        RECT 596.250 1130.000 596.530 1130.280 ;
    END
  END ciphertext[80]
  PIN ciphertext[81]
    DIRECTION OUTPUT ;
    USE SIGNAL ;
    ANTENNAGATEAREA 0.126000 ;
    ANTENNADIFFAREA 0.429000 ;
    PORT
      LAYER met2 ;
        RECT 618.330 1130.000 618.610 1130.280 ;
    END
  END ciphertext[81]
  PIN ciphertext[82]
    DIRECTION OUTPUT ;
    USE SIGNAL ;
    ANTENNAGATEAREA 0.126000 ;
    ANTENNADIFFAREA 0.429000 ;
    PORT
      LAYER met2 ;
        RECT 633.050 1130.000 633.330 1130.280 ;
    END
  END ciphertext[82]
  PIN ciphertext[83]
    DIRECTION OUTPUT ;
    USE SIGNAL ;
    ANTENNADIFFAREA 0.795200 ;
    PORT
      LAYER met2 ;
        RECT 627.530 1130.000 627.810 1130.280 ;
    END
  END ciphertext[83]
  PIN ciphertext[84]
    DIRECTION OUTPUT ;
    USE SIGNAL ;
    ANTENNAGATEAREA 0.126000 ;
    ANTENNADIFFAREA 0.429000 ;
    PORT
      LAYER met2 ;
        RECT 645.930 1130.000 646.210 1130.280 ;
    END
  END ciphertext[84]
  PIN ciphertext[85]
    DIRECTION OUTPUT ;
    USE SIGNAL ;
    ANTENNAGATEAREA 0.126000 ;
    ANTENNADIFFAREA 0.429000 ;
    PORT
      LAYER met2 ;
        RECT 628.450 1130.000 628.730 1130.280 ;
    END
  END ciphertext[85]
  PIN ciphertext[86]
    DIRECTION OUTPUT ;
    USE SIGNAL ;
    ANTENNADIFFAREA 0.702900 ;
    PORT
      LAYER met2 ;
        RECT 585.210 1130.000 585.490 1130.280 ;
    END
  END ciphertext[86]
  PIN ciphertext[87]
    DIRECTION OUTPUT ;
    USE SIGNAL ;
    ANTENNADIFFAREA 0.702900 ;
    PORT
      LAYER met2 ;
        RECT 576.930 1130.000 577.210 1130.280 ;
    END
  END ciphertext[87]
  PIN ciphertext[88]
    DIRECTION OUTPUT ;
    USE SIGNAL ;
    ANTENNADIFFAREA 0.383400 ;
    PORT
      LAYER met2 ;
        RECT 587.050 1130.000 587.330 1130.280 ;
    END
  END ciphertext[88]
  PIN ciphertext[89]
    DIRECTION OUTPUT ;
    USE SIGNAL ;
    ANTENNAGATEAREA 0.126000 ;
    ANTENNADIFFAREA 0.429000 ;
    PORT
      LAYER met2 ;
        RECT 606.370 1130.000 606.650 1130.280 ;
    END
  END ciphertext[89]
  PIN ciphertext[8]
    DIRECTION OUTPUT ;
    USE SIGNAL ;
    ANTENNADIFFAREA 0.702900 ;
    PORT
      LAYER met2 ;
        RECT 994.610 1130.000 994.890 1130.280 ;
    END
  END ciphertext[8]
  PIN ciphertext[90]
    DIRECTION OUTPUT ;
    USE SIGNAL ;
    ANTENNADIFFAREA 0.795200 ;
    PORT
      LAYER met2 ;
        RECT 629.370 1130.000 629.650 1130.280 ;
    END
  END ciphertext[90]
  PIN ciphertext[91]
    DIRECTION OUTPUT ;
    USE SIGNAL ;
    ANTENNADIFFAREA 0.702900 ;
    PORT
      LAYER met2 ;
        RECT 646.850 1130.000 647.130 1130.280 ;
    END
  END ciphertext[91]
  PIN ciphertext[92]
    DIRECTION OUTPUT ;
    USE SIGNAL ;
    ANTENNAGATEAREA 0.126000 ;
    ANTENNADIFFAREA 0.429000 ;
    PORT
      LAYER met2 ;
        RECT 630.290 1130.000 630.570 1130.280 ;
    END
  END ciphertext[92]
  PIN ciphertext[93]
    DIRECTION OUTPUT ;
    USE SIGNAL ;
    ANTENNAGATEAREA 0.126000 ;
    ANTENNADIFFAREA 0.429000 ;
    PORT
      LAYER met2 ;
        RECT 594.410 1130.000 594.690 1130.280 ;
    END
  END ciphertext[93]
  PIN ciphertext[94]
    DIRECTION OUTPUT ;
    USE SIGNAL ;
    ANTENNADIFFAREA 0.702900 ;
    PORT
      LAYER met2 ;
        RECT 574.170 1130.000 574.450 1130.280 ;
    END
  END ciphertext[94]
  PIN ciphertext[95]
    DIRECTION OUTPUT ;
    USE SIGNAL ;
    ANTENNAGATEAREA 0.126000 ;
    ANTENNADIFFAREA 0.429000 ;
    PORT
      LAYER met2 ;
        RECT 576.010 1130.000 576.290 1130.280 ;
    END
  END ciphertext[95]
  PIN ciphertext[96]
    DIRECTION OUTPUT ;
    USE SIGNAL ;
    ANTENNAGATEAREA 0.126000 ;
    ANTENNADIFFAREA 0.429000 ;
    PORT
      LAYER met3 ;
        RECT 1118.960 228.520 1119.560 229.120 ;
    END
  END ciphertext[96]
  PIN ciphertext[97]
    DIRECTION OUTPUT ;
    USE SIGNAL ;
    ANTENNADIFFAREA 0.383400 ;
    PORT
      LAYER met3 ;
        RECT 1118.960 308.760 1119.560 309.360 ;
    END
  END ciphertext[97]
  PIN ciphertext[98]
    DIRECTION OUTPUT ;
    USE SIGNAL ;
    ANTENNAGATEAREA 0.126000 ;
    ANTENNADIFFAREA 0.429000 ;
    PORT
      LAYER met3 ;
        RECT 1118.960 307.400 1119.560 308.000 ;
    END
  END ciphertext[98]
  PIN ciphertext[99]
    DIRECTION OUTPUT ;
    USE SIGNAL ;
    ANTENNAGATEAREA 0.126000 ;
    ANTENNADIFFAREA 0.429000 ;
    PORT
      LAYER met3 ;
        RECT 1118.960 243.480 1119.560 244.080 ;
    END
  END ciphertext[99]
  PIN ciphertext[9]
    DIRECTION OUTPUT ;
    USE SIGNAL ;
    ANTENNAGATEAREA 0.126000 ;
    ANTENNADIFFAREA 0.429000 ;
    PORT
      LAYER met2 ;
        RECT 1005.650 1130.000 1005.930 1130.280 ;
    END
  END ciphertext[9]
  PIN clk
    DIRECTION INPUT ;
    USE SIGNAL ;
    ANTENNAGATEAREA 0.852000 ;
    PORT
      LAYER met3 ;
        RECT 1118.960 224.440 1119.560 225.040 ;
    END
  END clk
  PIN done
    DIRECTION OUTPUT ;
    USE SIGNAL ;
    ANTENNADIFFAREA 0.702900 ;
    PORT
      LAYER met3 ;
        RECT 1118.960 233.960 1119.560 234.560 ;
    END
  END done
  PIN key[0]
    DIRECTION INPUT ;
    USE SIGNAL ;
    ANTENNAGATEAREA 0.159000 ;
    PORT
      LAYER met3 ;
        RECT 1118.960 403.960 1119.560 404.560 ;
    END
  END key[0]
  PIN key[100]
    DIRECTION INPUT ;
    USE SIGNAL ;
    ANTENNAGATEAREA 0.247500 ;
    PORT
      LAYER met3 ;
        RECT 0.000 559.000 0.600 559.600 ;
    END
  END key[100]
  PIN key[101]
    DIRECTION INPUT ;
    USE SIGNAL ;
    ANTENNAGATEAREA 0.196500 ;
    PORT
      LAYER met3 ;
        RECT 1118.960 273.400 1119.560 274.000 ;
    END
  END key[101]
  PIN key[102]
    DIRECTION INPUT ;
    USE SIGNAL ;
    ANTENNAGATEAREA 0.159000 ;
    PORT
      LAYER met3 ;
        RECT 1118.960 274.760 1119.560 275.360 ;
    END
  END key[102]
  PIN key[103]
    DIRECTION INPUT ;
    USE SIGNAL ;
    ANTENNAGATEAREA 0.247500 ;
    PORT
      LAYER met2 ;
        RECT 191.450 0.000 191.730 0.280 ;
    END
  END key[103]
  PIN key[104]
    DIRECTION INPUT ;
    USE SIGNAL ;
    ANTENNAGATEAREA 0.495000 ;
    PORT
      LAYER met2 ;
        RECT 369.930 0.000 370.210 0.280 ;
    END
  END key[104]
  PIN key[105]
    DIRECTION INPUT ;
    USE SIGNAL ;
    ANTENNAGATEAREA 0.159000 ;
    PORT
      LAYER met2 ;
        RECT 370.850 0.000 371.130 0.280 ;
    END
  END key[105]
  PIN key[106]
    DIRECTION INPUT ;
    USE SIGNAL ;
    ANTENNAGATEAREA 0.247500 ;
    PORT
      LAYER met2 ;
        RECT 226.410 0.000 226.690 0.280 ;
    END
  END key[106]
  PIN key[107]
    DIRECTION INPUT ;
    USE SIGNAL ;
    ANTENNAGATEAREA 0.247500 ;
    PORT
      LAYER met2 ;
        RECT 215.370 0.000 215.650 0.280 ;
    END
  END key[107]
  PIN key[108]
    DIRECTION INPUT ;
    USE SIGNAL ;
    ANTENNAGATEAREA 0.247500 ;
    PORT
      LAYER met2 ;
        RECT 210.770 0.000 211.050 0.280 ;
    END
  END key[108]
  PIN key[109]
    DIRECTION INPUT ;
    USE SIGNAL ;
    ANTENNAGATEAREA 0.247500 ;
    PORT
      LAYER met2 ;
        RECT 221.810 0.000 222.090 0.280 ;
    END
  END key[109]
  PIN key[10]
    DIRECTION INPUT ;
    USE SIGNAL ;
    ANTENNAGATEAREA 0.159000 ;
    PORT
      LAYER met3 ;
        RECT 1118.960 383.560 1119.560 384.160 ;
    END
  END key[10]
  PIN key[110]
    DIRECTION INPUT ;
    USE SIGNAL ;
    ANTENNAGATEAREA 0.247500 ;
    PORT
      LAYER met2 ;
        RECT 217.210 0.000 217.490 0.280 ;
    END
  END key[110]
  PIN key[111]
    DIRECTION INPUT ;
    USE SIGNAL ;
    ANTENNAGATEAREA 0.196500 ;
    PORT
      LAYER met3 ;
        RECT 1118.960 276.120 1119.560 276.720 ;
    END
  END key[111]
  PIN key[112]
    DIRECTION INPUT ;
    USE SIGNAL ;
    ANTENNAGATEAREA 0.247500 ;
    PORT
      LAYER met3 ;
        RECT 0.000 572.600 0.600 573.200 ;
    END
  END key[112]
  PIN key[113]
    DIRECTION INPUT ;
    USE SIGNAL ;
    ANTENNAGATEAREA 0.247500 ;
    PORT
      LAYER met3 ;
        RECT 0.000 583.480 0.600 584.080 ;
    END
  END key[113]
  PIN key[114]
    DIRECTION INPUT ;
    USE SIGNAL ;
    ANTENNAGATEAREA 0.247500 ;
    PORT
      LAYER met3 ;
        RECT 0.000 582.120 0.600 582.720 ;
    END
  END key[114]
  PIN key[115]
    DIRECTION INPUT ;
    USE SIGNAL ;
    ANTENNAGATEAREA 0.247500 ;
    PORT
      LAYER met3 ;
        RECT 0.000 580.760 0.600 581.360 ;
    END
  END key[115]
  PIN key[116]
    DIRECTION INPUT ;
    USE SIGNAL ;
    ANTENNAGATEAREA 0.247500 ;
    PORT
      LAYER met3 ;
        RECT 0.000 579.400 0.600 580.000 ;
    END
  END key[116]
  PIN key[117]
    DIRECTION INPUT ;
    USE SIGNAL ;
    ANTENNAGATEAREA 0.247500 ;
    PORT
      LAYER met3 ;
        RECT 0.000 578.040 0.600 578.640 ;
    END
  END key[117]
  PIN key[118]
    DIRECTION INPUT ;
    USE SIGNAL ;
    ANTENNAGATEAREA 0.247500 ;
    PORT
      LAYER met3 ;
        RECT 0.000 576.680 0.600 577.280 ;
    END
  END key[118]
  PIN key[119]
    DIRECTION INPUT ;
    USE SIGNAL ;
    ANTENNAGATEAREA 0.247500 ;
    PORT
      LAYER met3 ;
        RECT 0.000 575.320 0.600 575.920 ;
    END
  END key[119]
  PIN key[11]
    DIRECTION INPUT ;
    USE SIGNAL ;
    ANTENNAGATEAREA 0.247500 ;
    PORT
      LAYER met3 ;
        RECT 1118.960 545.400 1119.560 546.000 ;
    END
  END key[11]
  PIN key[120]
    DIRECTION INPUT ;
    USE SIGNAL ;
    ANTENNAGATEAREA 0.213000 ;
    PORT
      LAYER met3 ;
        RECT 1118.960 277.480 1119.560 278.080 ;
    END
  END key[120]
  PIN key[121]
    DIRECTION INPUT ;
    USE SIGNAL ;
    ANTENNAGATEAREA 0.495000 ;
    PORT
      LAYER met2 ;
        RECT 231.010 0.000 231.290 0.280 ;
    END
  END key[121]
  PIN key[122]
    DIRECTION INPUT ;
    USE SIGNAL ;
    ANTENNAGATEAREA 0.247500 ;
    PORT
      LAYER met3 ;
        RECT 0.000 573.960 0.600 574.560 ;
    END
  END key[122]
  PIN key[123]
    DIRECTION INPUT ;
    USE SIGNAL ;
    ANTENNAGATEAREA 0.247500 ;
    PORT
      LAYER met3 ;
        RECT 0.000 571.240 0.600 571.840 ;
    END
  END key[123]
  PIN key[124]
    DIRECTION INPUT ;
    USE SIGNAL ;
    ANTENNAGATEAREA 0.247500 ;
    PORT
      LAYER met3 ;
        RECT 0.000 569.880 0.600 570.480 ;
    END
  END key[124]
  PIN key[125]
    DIRECTION INPUT ;
    USE SIGNAL ;
    ANTENNAGATEAREA 0.196500 ;
    PORT
      LAYER met3 ;
        RECT 1118.960 278.840 1119.560 279.440 ;
    END
  END key[125]
  PIN key[126]
    DIRECTION INPUT ;
    USE SIGNAL ;
    ANTENNAGATEAREA 0.196500 ;
    PORT
      LAYER met3 ;
        RECT 1118.960 280.200 1119.560 280.800 ;
    END
  END key[126]
  PIN key[127]
    DIRECTION INPUT ;
    USE SIGNAL ;
    ANTENNAGATEAREA 0.247500 ;
    PORT
      LAYER met2 ;
        RECT 185.930 0.000 186.210 0.280 ;
    END
  END key[127]
  PIN key[12]
    DIRECTION INPUT ;
    USE SIGNAL ;
    ANTENNAGATEAREA 0.159000 ;
    PORT
      LAYER met3 ;
        RECT 1118.960 546.760 1119.560 547.360 ;
    END
  END key[12]
  PIN key[13]
    DIRECTION INPUT ;
    USE SIGNAL ;
    ANTENNAGATEAREA 0.159000 ;
    PORT
      LAYER met3 ;
        RECT 1118.960 548.120 1119.560 548.720 ;
    END
  END key[13]
  PIN key[14]
    DIRECTION INPUT ;
    USE SIGNAL ;
    ANTENNAGATEAREA 0.159000 ;
    PORT
      LAYER met3 ;
        RECT 1118.960 549.480 1119.560 550.080 ;
    END
  END key[14]
  PIN key[15]
    DIRECTION INPUT ;
    USE SIGNAL ;
    ANTENNAGATEAREA 0.159000 ;
    PORT
      LAYER met3 ;
        RECT 1118.960 550.840 1119.560 551.440 ;
    END
  END key[15]
  PIN key[16]
    DIRECTION INPUT ;
    USE SIGNAL ;
    ANTENNAGATEAREA 0.247500 ;
    PORT
      LAYER met3 ;
        RECT 1118.960 394.440 1119.560 395.040 ;
    END
  END key[16]
  PIN key[17]
    DIRECTION INPUT ;
    USE SIGNAL ;
    ANTENNAGATEAREA 0.159000 ;
    PORT
      LAYER met3 ;
        RECT 1118.960 374.040 1119.560 374.640 ;
    END
  END key[17]
  PIN key[18]
    DIRECTION INPUT ;
    USE SIGNAL ;
    ANTENNAGATEAREA 0.159000 ;
    PORT
      LAYER met3 ;
        RECT 1118.960 552.200 1119.560 552.800 ;
    END
  END key[18]
  PIN key[19]
    DIRECTION INPUT ;
    USE SIGNAL ;
    ANTENNAGATEAREA 0.247500 ;
    PORT
      LAYER met3 ;
        RECT 1118.960 386.280 1119.560 386.880 ;
    END
  END key[19]
  PIN key[1]
    DIRECTION INPUT ;
    USE SIGNAL ;
    ANTENNAGATEAREA 0.247500 ;
    PORT
      LAYER met3 ;
        RECT 1118.960 376.760 1119.560 377.360 ;
    END
  END key[1]
  PIN key[20]
    DIRECTION INPUT ;
    USE SIGNAL ;
    ANTENNAGATEAREA 0.159000 ;
    PORT
      LAYER met3 ;
        RECT 1118.960 553.560 1119.560 554.160 ;
    END
  END key[20]
  PIN key[21]
    DIRECTION INPUT ;
    USE SIGNAL ;
    ANTENNAGATEAREA 0.159000 ;
    PORT
      LAYER met3 ;
        RECT 1118.960 554.920 1119.560 555.520 ;
    END
  END key[21]
  PIN key[22]
    DIRECTION INPUT ;
    USE SIGNAL ;
    ANTENNAGATEAREA 0.159000 ;
    PORT
      LAYER met3 ;
        RECT 1118.960 556.280 1119.560 556.880 ;
    END
  END key[22]
  PIN key[23]
    DIRECTION INPUT ;
    USE SIGNAL ;
    ANTENNAGATEAREA 0.159000 ;
    PORT
      LAYER met3 ;
        RECT 1118.960 557.640 1119.560 558.240 ;
    END
  END key[23]
  PIN key[24]
    DIRECTION INPUT ;
    USE SIGNAL ;
    ANTENNAGATEAREA 0.196500 ;
    PORT
      LAYER met2 ;
        RECT 932.970 1130.000 933.250 1130.280 ;
    END
  END key[24]
  PIN key[25]
    DIRECTION INPUT ;
    USE SIGNAL ;
    ANTENNAGATEAREA 0.213000 ;
    PORT
      LAYER met2 ;
        RECT 932.050 1130.000 932.330 1130.280 ;
    END
  END key[25]
  PIN key[26]
    DIRECTION INPUT ;
    USE SIGNAL ;
    ANTENNAGATEAREA 0.159000 ;
    PORT
      LAYER met3 ;
        RECT 1118.960 387.640 1119.560 388.240 ;
    END
  END key[26]
  PIN key[27]
    DIRECTION INPUT ;
    USE SIGNAL ;
    ANTENNAGATEAREA 0.247500 ;
    PORT
      LAYER met2 ;
        RECT 931.130 1130.000 931.410 1130.280 ;
    END
  END key[27]
  PIN key[28]
    DIRECTION INPUT ;
    USE SIGNAL ;
    ANTENNAGATEAREA 0.159000 ;
    PORT
      LAYER met3 ;
        RECT 1118.960 559.000 1119.560 559.600 ;
    END
  END key[28]
  PIN key[29]
    DIRECTION INPUT ;
    USE SIGNAL ;
    ANTENNAGATEAREA 0.159000 ;
    PORT
      LAYER met3 ;
        RECT 1118.960 560.360 1119.560 560.960 ;
    END
  END key[29]
  PIN key[2]
    DIRECTION INPUT ;
    USE SIGNAL ;
    ANTENNAGATEAREA 0.159000 ;
    PORT
      LAYER met3 ;
        RECT 1118.960 369.960 1119.560 370.560 ;
    END
  END key[2]
  PIN key[30]
    DIRECTION INPUT ;
    USE SIGNAL ;
    ANTENNAGATEAREA 0.159000 ;
    PORT
      LAYER met3 ;
        RECT 1118.960 561.720 1119.560 562.320 ;
    END
  END key[30]
  PIN key[31]
    DIRECTION INPUT ;
    USE SIGNAL ;
    ANTENNAGATEAREA 0.159000 ;
    PORT
      LAYER met3 ;
        RECT 1118.960 563.080 1119.560 563.680 ;
    END
  END key[31]
  PIN key[32]
    DIRECTION INPUT ;
    USE SIGNAL ;
    ANTENNAGATEAREA 0.247500 ;
    PORT
      LAYER met2 ;
        RECT 186.850 0.000 187.130 0.280 ;
    END
  END key[32]
  PIN key[33]
    DIRECTION INPUT ;
    USE SIGNAL ;
    ANTENNAGATEAREA 0.196500 ;
    PORT
      LAYER met3 ;
        RECT 0.000 296.520 0.600 297.120 ;
    END
  END key[33]
  PIN key[34]
    DIRECTION INPUT ;
    USE SIGNAL ;
    ANTENNAGATEAREA 0.247500 ;
    PORT
      LAYER met2 ;
        RECT 187.770 0.000 188.050 0.280 ;
    END
  END key[34]
  PIN key[35]
    DIRECTION INPUT ;
    USE SIGNAL ;
    ANTENNAGATEAREA 0.159000 ;
    PORT
      LAYER met2 ;
        RECT 188.690 0.000 188.970 0.280 ;
    END
  END key[35]
  PIN key[36]
    DIRECTION INPUT ;
    USE SIGNAL ;
    ANTENNAGATEAREA 0.159000 ;
    PORT
      LAYER met3 ;
        RECT 0.000 311.480 0.600 312.080 ;
    END
  END key[36]
  PIN key[37]
    DIRECTION INPUT ;
    USE SIGNAL ;
    ANTENNAGATEAREA 0.159000 ;
    PORT
      LAYER met2 ;
        RECT 189.610 0.000 189.890 0.280 ;
    END
  END key[37]
  PIN key[38]
    DIRECTION INPUT ;
    USE SIGNAL ;
    ANTENNAGATEAREA 0.159000 ;
    PORT
      LAYER met2 ;
        RECT 190.530 0.000 190.810 0.280 ;
    END
  END key[38]
  PIN key[39]
    DIRECTION INPUT ;
    USE SIGNAL ;
    ANTENNAGATEAREA 0.159000 ;
    PORT
      LAYER met2 ;
        RECT 192.370 0.000 192.650 0.280 ;
    END
  END key[39]
  PIN key[3]
    DIRECTION INPUT ;
    USE SIGNAL ;
    ANTENNAGATEAREA 0.159000 ;
    PORT
      LAYER met3 ;
        RECT 1118.960 378.120 1119.560 378.720 ;
    END
  END key[3]
  PIN key[40]
    DIRECTION INPUT ;
    USE SIGNAL ;
    ANTENNAGATEAREA 0.159000 ;
    PORT
      LAYER met2 ;
        RECT 193.290 0.000 193.570 0.280 ;
    END
  END key[40]
  PIN key[41]
    DIRECTION INPUT ;
    USE SIGNAL ;
    ANTENNAGATEAREA 0.247500 ;
    PORT
      LAYER met3 ;
        RECT 0.000 308.760 0.600 309.360 ;
    END
  END key[41]
  PIN key[42]
    DIRECTION INPUT ;
    USE SIGNAL ;
    ANTENNAGATEAREA 0.196500 ;
    PORT
      LAYER met2 ;
        RECT 194.210 0.000 194.490 0.280 ;
    END
  END key[42]
  PIN key[43]
    DIRECTION INPUT ;
    USE SIGNAL ;
    ANTENNAGATEAREA 0.159000 ;
    PORT
      LAYER met3 ;
        RECT 0.000 307.400 0.600 308.000 ;
    END
  END key[43]
  PIN key[44]
    DIRECTION INPUT ;
    USE SIGNAL ;
    ANTENNAGATEAREA 0.159000 ;
    PORT
      LAYER met2 ;
        RECT 195.130 0.000 195.410 0.280 ;
    END
  END key[44]
  PIN key[45]
    DIRECTION INPUT ;
    USE SIGNAL ;
    ANTENNAGATEAREA 0.159000 ;
    PORT
      LAYER met2 ;
        RECT 196.050 0.000 196.330 0.280 ;
    END
  END key[45]
  PIN key[46]
    DIRECTION INPUT ;
    USE SIGNAL ;
    ANTENNAGATEAREA 0.159000 ;
    PORT
      LAYER met2 ;
        RECT 196.970 0.000 197.250 0.280 ;
    END
  END key[46]
  PIN key[47]
    DIRECTION INPUT ;
    USE SIGNAL ;
    ANTENNAGATEAREA 0.159000 ;
    PORT
      LAYER met2 ;
        RECT 197.890 0.000 198.170 0.280 ;
    END
  END key[47]
  PIN key[48]
    DIRECTION INPUT ;
    USE SIGNAL ;
    ANTENNAGATEAREA 0.247500 ;
    PORT
      LAYER met3 ;
        RECT 0.000 306.040 0.600 306.640 ;
    END
  END key[48]
  PIN key[49]
    DIRECTION INPUT ;
    USE SIGNAL ;
    ANTENNAGATEAREA 0.159000 ;
    PORT
      LAYER met3 ;
        RECT 0.000 304.680 0.600 305.280 ;
    END
  END key[49]
  PIN key[4]
    DIRECTION INPUT ;
    USE SIGNAL ;
    ANTENNAGATEAREA 0.159000 ;
    PORT
      LAYER met3 ;
        RECT 1118.960 405.320 1119.560 405.920 ;
    END
  END key[4]
  PIN key[50]
    DIRECTION INPUT ;
    USE SIGNAL ;
    ANTENNAGATEAREA 0.159000 ;
    PORT
      LAYER met3 ;
        RECT 0.000 297.880 0.600 298.480 ;
    END
  END key[50]
  PIN key[51]
    DIRECTION INPUT ;
    USE SIGNAL ;
    ANTENNAGATEAREA 0.247500 ;
    PORT
      LAYER met3 ;
        RECT 0.000 301.960 0.600 302.560 ;
    END
  END key[51]
  PIN key[52]
    DIRECTION INPUT ;
    USE SIGNAL ;
    ANTENNAGATEAREA 0.159000 ;
    PORT
      LAYER met3 ;
        RECT 0.000 300.600 0.600 301.200 ;
    END
  END key[52]
  PIN key[53]
    DIRECTION INPUT ;
    USE SIGNAL ;
    ANTENNAGATEAREA 0.159000 ;
    PORT
      LAYER met2 ;
        RECT 90.250 0.000 90.530 0.280 ;
    END
  END key[53]
  PIN key[54]
    DIRECTION INPUT ;
    USE SIGNAL ;
    ANTENNAGATEAREA 0.159000 ;
    PORT
      LAYER met2 ;
        RECT 89.330 0.000 89.610 0.280 ;
    END
  END key[54]
  PIN key[55]
    DIRECTION INPUT ;
    USE SIGNAL ;
    ANTENNAGATEAREA 0.159000 ;
    PORT
      LAYER met3 ;
        RECT 0.000 299.240 0.600 299.840 ;
    END
  END key[55]
  PIN key[56]
    DIRECTION INPUT ;
    USE SIGNAL ;
    ANTENNAGATEAREA 0.247500 ;
    PORT
      LAYER met2 ;
        RECT 198.810 0.000 199.090 0.280 ;
    END
  END key[56]
  PIN key[57]
    DIRECTION INPUT ;
    USE SIGNAL ;
    ANTENNAGATEAREA 0.159000 ;
    PORT
      LAYER met3 ;
        RECT 0.000 262.520 0.600 263.120 ;
    END
  END key[57]
  PIN key[58]
    DIRECTION INPUT ;
    USE SIGNAL ;
    ANTENNAGATEAREA 0.247500 ;
    PORT
      LAYER met2 ;
        RECT 211.690 0.000 211.970 0.280 ;
    END
  END key[58]
  PIN key[59]
    DIRECTION INPUT ;
    USE SIGNAL ;
    ANTENNAGATEAREA 0.247500 ;
    PORT
      LAYER met2 ;
        RECT 199.730 0.000 200.010 0.280 ;
    END
  END key[59]
  PIN key[5]
    DIRECTION INPUT ;
    USE SIGNAL ;
    ANTENNAGATEAREA 0.159000 ;
    PORT
      LAYER met3 ;
        RECT 1118.960 401.240 1119.560 401.840 ;
    END
  END key[5]
  PIN key[60]
    DIRECTION INPUT ;
    USE SIGNAL ;
    ANTENNAGATEAREA 0.159000 ;
    PORT
      LAYER met2 ;
        RECT 200.650 0.000 200.930 0.280 ;
    END
  END key[60]
  PIN key[61]
    DIRECTION INPUT ;
    USE SIGNAL ;
    ANTENNAGATEAREA 0.159000 ;
    PORT
      LAYER met2 ;
        RECT 201.570 0.000 201.850 0.280 ;
    END
  END key[61]
  PIN key[62]
    DIRECTION INPUT ;
    USE SIGNAL ;
    ANTENNAGATEAREA 0.159000 ;
    PORT
      LAYER met2 ;
        RECT 202.490 0.000 202.770 0.280 ;
    END
  END key[62]
  PIN key[63]
    DIRECTION INPUT ;
    USE SIGNAL ;
    ANTENNAGATEAREA 0.159000 ;
    PORT
      LAYER met2 ;
        RECT 203.410 0.000 203.690 0.280 ;
    END
  END key[63]
  PIN key[64]
    DIRECTION INPUT ;
    USE SIGNAL ;
    ANTENNAGATEAREA 0.159000 ;
    PORT
      LAYER met2 ;
        RECT 380.970 1130.000 381.250 1130.280 ;
    END
  END key[64]
  PIN key[65]
    DIRECTION INPUT ;
    USE SIGNAL ;
    ANTENNAGATEAREA 0.159000 ;
    PORT
      LAYER met2 ;
        RECT 564.970 1130.000 565.250 1130.280 ;
    END
  END key[65]
  PIN key[66]
    DIRECTION INPUT ;
    USE SIGNAL ;
    ANTENNAGATEAREA 0.159000 ;
    PORT
      LAYER met2 ;
        RECT 564.050 1130.000 564.330 1130.280 ;
    END
  END key[66]
  PIN key[67]
    DIRECTION INPUT ;
    USE SIGNAL ;
    ANTENNAGATEAREA 0.247500 ;
    PORT
      LAYER met2 ;
        RECT 563.130 1130.000 563.410 1130.280 ;
    END
  END key[67]
  PIN key[68]
    DIRECTION INPUT ;
    USE SIGNAL ;
    ANTENNAGATEAREA 0.159000 ;
    PORT
      LAYER met2 ;
        RECT 562.210 1130.000 562.490 1130.280 ;
    END
  END key[68]
  PIN key[69]
    DIRECTION INPUT ;
    USE SIGNAL ;
    ANTENNAGATEAREA 0.196500 ;
    PORT
      LAYER met2 ;
        RECT 561.290 1130.000 561.570 1130.280 ;
    END
  END key[69]
  PIN key[6]
    DIRECTION INPUT ;
    USE SIGNAL ;
    ANTENNAGATEAREA 0.159000 ;
    PORT
      LAYER met3 ;
        RECT 1118.960 564.440 1119.560 565.040 ;
    END
  END key[6]
  PIN key[70]
    DIRECTION INPUT ;
    USE SIGNAL ;
    ANTENNAGATEAREA 0.196500 ;
    PORT
      LAYER met2 ;
        RECT 560.370 1130.000 560.650 1130.280 ;
    END
  END key[70]
  PIN key[71]
    DIRECTION INPUT ;
    USE SIGNAL ;
    ANTENNAGATEAREA 0.196500 ;
    PORT
      LAYER met2 ;
        RECT 559.450 1130.000 559.730 1130.280 ;
    END
  END key[71]
  PIN key[72]
    DIRECTION INPUT ;
    USE SIGNAL ;
    ANTENNAGATEAREA 0.247500 ;
    PORT
      LAYER met2 ;
        RECT 558.530 1130.000 558.810 1130.280 ;
    END
  END key[72]
  PIN key[73]
    DIRECTION INPUT ;
    USE SIGNAL ;
    ANTENNAGATEAREA 0.159000 ;
    PORT
      LAYER met2 ;
        RECT 557.610 1130.000 557.890 1130.280 ;
    END
  END key[73]
  PIN key[74]
    DIRECTION INPUT ;
    USE SIGNAL ;
    ANTENNAGATEAREA 0.196500 ;
    PORT
      LAYER met2 ;
        RECT 556.690 1130.000 556.970 1130.280 ;
    END
  END key[74]
  PIN key[75]
    DIRECTION INPUT ;
    USE SIGNAL ;
    ANTENNAGATEAREA 0.196500 ;
    PORT
      LAYER met2 ;
        RECT 555.770 1130.000 556.050 1130.280 ;
    END
  END key[75]
  PIN key[76]
    DIRECTION INPUT ;
    USE SIGNAL ;
    ANTENNAGATEAREA 0.196500 ;
    PORT
      LAYER met2 ;
        RECT 554.850 1130.000 555.130 1130.280 ;
    END
  END key[76]
  PIN key[77]
    DIRECTION INPUT ;
    USE SIGNAL ;
    ANTENNAGATEAREA 0.196500 ;
    PORT
      LAYER met2 ;
        RECT 553.930 1130.000 554.210 1130.280 ;
    END
  END key[77]
  PIN key[78]
    DIRECTION INPUT ;
    USE SIGNAL ;
    ANTENNAGATEAREA 0.196500 ;
    PORT
      LAYER met2 ;
        RECT 553.010 1130.000 553.290 1130.280 ;
    END
  END key[78]
  PIN key[79]
    DIRECTION INPUT ;
    USE SIGNAL ;
    ANTENNAGATEAREA 0.196500 ;
    PORT
      LAYER met2 ;
        RECT 552.090 1130.000 552.370 1130.280 ;
    END
  END key[79]
  PIN key[7]
    DIRECTION INPUT ;
    USE SIGNAL ;
    ANTENNAGATEAREA 0.159000 ;
    PORT
      LAYER met3 ;
        RECT 1118.960 565.800 1119.560 566.400 ;
    END
  END key[7]
  PIN key[80]
    DIRECTION INPUT ;
    USE SIGNAL ;
    ANTENNAGATEAREA 0.196500 ;
    PORT
      LAYER met2 ;
        RECT 551.170 1130.000 551.450 1130.280 ;
    END
  END key[80]
  PIN key[81]
    DIRECTION INPUT ;
    USE SIGNAL ;
    ANTENNAGATEAREA 0.159000 ;
    PORT
      LAYER met3 ;
        RECT 0.000 1018.680 0.600 1019.280 ;
    END
  END key[81]
  PIN key[82]
    DIRECTION INPUT ;
    USE SIGNAL ;
    ANTENNAGATEAREA 0.247500 ;
    PORT
      LAYER met2 ;
        RECT 550.250 1130.000 550.530 1130.280 ;
    END
  END key[82]
  PIN key[83]
    DIRECTION INPUT ;
    USE SIGNAL ;
    ANTENNAGATEAREA 0.196500 ;
    PORT
      LAYER met2 ;
        RECT 549.330 1130.000 549.610 1130.280 ;
    END
  END key[83]
  PIN key[84]
    DIRECTION INPUT ;
    USE SIGNAL ;
    ANTENNAGATEAREA 0.159000 ;
    PORT
      LAYER met3 ;
        RECT 0.000 1015.960 0.600 1016.560 ;
    END
  END key[84]
  PIN key[85]
    DIRECTION INPUT ;
    USE SIGNAL ;
    ANTENNAGATEAREA 0.196500 ;
    PORT
      LAYER met2 ;
        RECT 548.410 1130.000 548.690 1130.280 ;
    END
  END key[85]
  PIN key[86]
    DIRECTION INPUT ;
    USE SIGNAL ;
    ANTENNAGATEAREA 0.196500 ;
    PORT
      LAYER met2 ;
        RECT 547.490 1130.000 547.770 1130.280 ;
    END
  END key[86]
  PIN key[87]
    DIRECTION INPUT ;
    USE SIGNAL ;
    ANTENNAGATEAREA 0.196500 ;
    PORT
      LAYER met2 ;
        RECT 546.570 1130.000 546.850 1130.280 ;
    END
  END key[87]
  PIN key[88]
    DIRECTION INPUT ;
    USE SIGNAL ;
    ANTENNAGATEAREA 0.196500 ;
    PORT
      LAYER met2 ;
        RECT 545.650 1130.000 545.930 1130.280 ;
    END
  END key[88]
  PIN key[89]
    DIRECTION INPUT ;
    USE SIGNAL ;
    ANTENNAGATEAREA 0.247500 ;
    PORT
      LAYER met2 ;
        RECT 544.730 1130.000 545.010 1130.280 ;
    END
  END key[89]
  PIN key[8]
    DIRECTION INPUT ;
    USE SIGNAL ;
    ANTENNAGATEAREA 0.159000 ;
    PORT
      LAYER met3 ;
        RECT 1118.960 567.160 1119.560 567.760 ;
    END
  END key[8]
  PIN key[90]
    DIRECTION INPUT ;
    USE SIGNAL ;
    ANTENNAGATEAREA 0.247500 ;
    PORT
      LAYER met2 ;
        RECT 479.410 1130.000 479.690 1130.280 ;
    END
  END key[90]
  PIN key[91]
    DIRECTION INPUT ;
    USE SIGNAL ;
    ANTENNAGATEAREA 0.196500 ;
    PORT
      LAYER met2 ;
        RECT 543.810 1130.000 544.090 1130.280 ;
    END
  END key[91]
  PIN key[92]
    DIRECTION INPUT ;
    USE SIGNAL ;
    ANTENNAGATEAREA 0.196500 ;
    PORT
      LAYER met2 ;
        RECT 542.890 1130.000 543.170 1130.280 ;
    END
  END key[92]
  PIN key[93]
    DIRECTION INPUT ;
    USE SIGNAL ;
    ANTENNAGATEAREA 0.196500 ;
    PORT
      LAYER met2 ;
        RECT 541.970 1130.000 542.250 1130.280 ;
    END
  END key[93]
  PIN key[94]
    DIRECTION INPUT ;
    USE SIGNAL ;
    ANTENNAGATEAREA 0.196500 ;
    PORT
      LAYER met2 ;
        RECT 541.050 1130.000 541.330 1130.280 ;
    END
  END key[94]
  PIN key[95]
    DIRECTION INPUT ;
    USE SIGNAL ;
    ANTENNAGATEAREA 0.196500 ;
    PORT
      LAYER met2 ;
        RECT 540.130 1130.000 540.410 1130.280 ;
    END
  END key[95]
  PIN key[96]
    DIRECTION INPUT ;
    USE SIGNAL ;
    ANTENNAGATEAREA 0.247500 ;
    PORT
      LAYER met3 ;
        RECT 0.000 568.520 0.600 569.120 ;
    END
  END key[96]
  PIN key[97]
    DIRECTION INPUT ;
    USE SIGNAL ;
    ANTENNAGATEAREA 0.247500 ;
    PORT
      LAYER met3 ;
        RECT 0.000 567.160 0.600 567.760 ;
    END
  END key[97]
  PIN key[98]
    DIRECTION INPUT ;
    USE SIGNAL ;
    ANTENNAGATEAREA 0.247500 ;
    PORT
      LAYER met3 ;
        RECT 1118.960 312.840 1119.560 313.440 ;
    END
  END key[98]
  PIN key[99]
    DIRECTION INPUT ;
    USE SIGNAL ;
    ANTENNAGATEAREA 0.159000 ;
    PORT
      LAYER met2 ;
        RECT 272.410 0.000 272.690 0.280 ;
    END
  END key[99]
  PIN key[9]
    DIRECTION INPUT ;
    USE SIGNAL ;
    ANTENNAGATEAREA 0.159000 ;
    PORT
      LAYER met3 ;
        RECT 1118.960 393.080 1119.560 393.680 ;
    END
  END key[9]
  PIN plaintext[0]
    DIRECTION INPUT ;
    USE SIGNAL ;
    ANTENNAGATEAREA 0.213000 ;
    PORT
      LAYER met3 ;
        RECT 1118.960 722.200 1119.560 722.800 ;
    END
  END plaintext[0]
  PIN plaintext[100]
    DIRECTION INPUT ;
    USE SIGNAL ;
    ANTENNAGATEAREA 0.159000 ;
    PORT
      LAYER met2 ;
        RECT 297.250 0.000 297.530 0.280 ;
    END
  END plaintext[100]
  PIN plaintext[101]
    DIRECTION INPUT ;
    USE SIGNAL ;
    ANTENNAGATEAREA 0.213000 ;
    PORT
      LAYER met3 ;
        RECT 0.000 428.440 0.600 429.040 ;
    END
  END plaintext[101]
  PIN plaintext[102]
    DIRECTION INPUT ;
    USE SIGNAL ;
    ANTENNAGATEAREA 0.213000 ;
    PORT
      LAYER met3 ;
        RECT 0.000 424.360 0.600 424.960 ;
    END
  END plaintext[102]
  PIN plaintext[103]
    DIRECTION INPUT ;
    USE SIGNAL ;
    ANTENNAGATEAREA 0.213000 ;
    PORT
      LAYER met3 ;
        RECT 0.000 420.280 0.600 420.880 ;
    END
  END plaintext[103]
  PIN plaintext[104]
    DIRECTION INPUT ;
    USE SIGNAL ;
    ANTENNAGATEAREA 0.213000 ;
    PORT
      LAYER met3 ;
        RECT 0.000 425.720 0.600 426.320 ;
    END
  END plaintext[104]
  PIN plaintext[105]
    DIRECTION INPUT ;
    USE SIGNAL ;
    ANTENNAGATEAREA 0.213000 ;
    PORT
      LAYER met3 ;
        RECT 0.000 413.480 0.600 414.080 ;
    END
  END plaintext[105]
  PIN plaintext[106]
    DIRECTION INPUT ;
    USE SIGNAL ;
    ANTENNAGATEAREA 0.213000 ;
    PORT
      LAYER met3 ;
        RECT 0.000 444.760 0.600 445.360 ;
    END
  END plaintext[106]
  PIN plaintext[107]
    DIRECTION INPUT ;
    USE SIGNAL ;
    ANTENNAGATEAREA 0.196500 ;
    PORT
      LAYER met3 ;
        RECT 0.000 418.920 0.600 419.520 ;
    END
  END plaintext[107]
  PIN plaintext[108]
    DIRECTION INPUT ;
    USE SIGNAL ;
    ANTENNAGATEAREA 0.213000 ;
    PORT
      LAYER met3 ;
        RECT 0.000 427.080 0.600 427.680 ;
    END
  END plaintext[108]
  PIN plaintext[109]
    DIRECTION INPUT ;
    USE SIGNAL ;
    ANTENNAGATEAREA 0.213000 ;
    PORT
      LAYER met3 ;
        RECT 0.000 491.000 0.600 491.600 ;
    END
  END plaintext[109]
  PIN plaintext[10]
    DIRECTION INPUT ;
    USE SIGNAL ;
    ANTENNAGATEAREA 0.196500 ;
    PORT
      LAYER met2 ;
        RECT 836.370 1130.000 836.650 1130.280 ;
    END
  END plaintext[10]
  PIN plaintext[110]
    DIRECTION INPUT ;
    USE SIGNAL ;
    ANTENNAGATEAREA 0.213000 ;
    PORT
      LAYER met3 ;
        RECT 0.000 431.160 0.600 431.760 ;
    END
  END plaintext[110]
  PIN plaintext[111]
    DIRECTION INPUT ;
    USE SIGNAL ;
    ANTENNAGATEAREA 0.213000 ;
    PORT
      LAYER met3 ;
        RECT 0.000 469.240 0.600 469.840 ;
    END
  END plaintext[111]
  PIN plaintext[112]
    DIRECTION INPUT ;
    USE SIGNAL ;
    ANTENNAGATEAREA 0.213000 ;
    PORT
      LAYER met3 ;
        RECT 0.000 402.600 0.600 403.200 ;
    END
  END plaintext[112]
  PIN plaintext[113]
    DIRECTION INPUT ;
    USE SIGNAL ;
    ANTENNAGATEAREA 0.213000 ;
    PORT
      LAYER met3 ;
        RECT 0.000 401.240 0.600 401.840 ;
    END
  END plaintext[113]
  PIN plaintext[114]
    DIRECTION INPUT ;
    USE SIGNAL ;
    ANTENNAGATEAREA 0.213000 ;
    PORT
      LAYER met3 ;
        RECT 0.000 403.960 0.600 404.560 ;
    END
  END plaintext[114]
  PIN plaintext[115]
    DIRECTION INPUT ;
    USE SIGNAL ;
    ANTENNAGATEAREA 0.213000 ;
    PORT
      LAYER met3 ;
        RECT 0.000 405.320 0.600 405.920 ;
    END
  END plaintext[115]
  PIN plaintext[116]
    DIRECTION INPUT ;
    USE SIGNAL ;
    ANTENNAGATEAREA 0.213000 ;
    PORT
      LAYER met3 ;
        RECT 0.000 412.120 0.600 412.720 ;
    END
  END plaintext[116]
  PIN plaintext[117]
    DIRECTION INPUT ;
    USE SIGNAL ;
    ANTENNAGATEAREA 0.213000 ;
    PORT
      LAYER met3 ;
        RECT 0.000 429.800 0.600 430.400 ;
    END
  END plaintext[117]
  PIN plaintext[118]
    DIRECTION INPUT ;
    USE SIGNAL ;
    ANTENNAGATEAREA 0.213000 ;
    PORT
      LAYER met3 ;
        RECT 0.000 436.600 0.600 437.200 ;
    END
  END plaintext[118]
  PIN plaintext[119]
    DIRECTION INPUT ;
    USE SIGNAL ;
    ANTENNAGATEAREA 0.213000 ;
    PORT
      LAYER met3 ;
        RECT 0.000 421.640 0.600 422.240 ;
    END
  END plaintext[119]
  PIN plaintext[11]
    DIRECTION INPUT ;
    USE SIGNAL ;
    ANTENNAGATEAREA 0.196500 ;
    PORT
      LAYER met2 ;
        RECT 842.810 1130.000 843.090 1130.280 ;
    END
  END plaintext[11]
  PIN plaintext[120]
    DIRECTION INPUT ;
    USE SIGNAL ;
    ANTENNAGATEAREA 0.213000 ;
    PORT
      LAYER met3 ;
        RECT 0.000 423.000 0.600 423.600 ;
    END
  END plaintext[120]
  PIN plaintext[121]
    DIRECTION INPUT ;
    USE SIGNAL ;
    ANTENNAGATEAREA 0.196500 ;
    PORT
      LAYER met3 ;
        RECT 0.000 340.040 0.600 340.640 ;
    END
  END plaintext[121]
  PIN plaintext[122]
    DIRECTION INPUT ;
    USE SIGNAL ;
    ANTENNAGATEAREA 0.213000 ;
    PORT
      LAYER met3 ;
        RECT 0.000 346.840 0.600 347.440 ;
    END
  END plaintext[122]
  PIN plaintext[123]
    DIRECTION INPUT ;
    USE SIGNAL ;
    ANTENNAGATEAREA 0.213000 ;
    PORT
      LAYER met3 ;
        RECT 0.000 335.960 0.600 336.560 ;
    END
  END plaintext[123]
  PIN plaintext[124]
    DIRECTION INPUT ;
    USE SIGNAL ;
    ANTENNAGATEAREA 0.213000 ;
    PORT
      LAYER met3 ;
        RECT 0.000 337.320 0.600 337.920 ;
    END
  END plaintext[124]
  PIN plaintext[125]
    DIRECTION INPUT ;
    USE SIGNAL ;
    ANTENNAGATEAREA 0.213000 ;
    PORT
      LAYER met3 ;
        RECT 0.000 333.240 0.600 333.840 ;
    END
  END plaintext[125]
  PIN plaintext[126]
    DIRECTION INPUT ;
    USE SIGNAL ;
    ANTENNAGATEAREA 0.213000 ;
    PORT
      LAYER met3 ;
        RECT 0.000 342.760 0.600 343.360 ;
    END
  END plaintext[126]
  PIN plaintext[127]
    DIRECTION INPUT ;
    USE SIGNAL ;
    ANTENNAGATEAREA 0.213000 ;
    PORT
      LAYER met3 ;
        RECT 0.000 414.840 0.600 415.440 ;
    END
  END plaintext[127]
  PIN plaintext[12]
    DIRECTION INPUT ;
    USE SIGNAL ;
    ANTENNAGATEAREA 0.196500 ;
    PORT
      LAYER met3 ;
        RECT 1118.960 738.520 1119.560 739.120 ;
    END
  END plaintext[12]
  PIN plaintext[13]
    DIRECTION INPUT ;
    USE SIGNAL ;
    ANTENNAGATEAREA 0.196500 ;
    PORT
      LAYER met3 ;
        RECT 1118.960 737.160 1119.560 737.760 ;
    END
  END plaintext[13]
  PIN plaintext[14]
    DIRECTION INPUT ;
    USE SIGNAL ;
    ANTENNAGATEAREA 0.196500 ;
    PORT
      LAYER met2 ;
        RECT 829.010 1130.000 829.290 1130.280 ;
    END
  END plaintext[14]
  PIN plaintext[15]
    DIRECTION INPUT ;
    USE SIGNAL ;
    ANTENNAGATEAREA 0.196500 ;
    PORT
      LAYER met2 ;
        RECT 847.410 1130.000 847.690 1130.280 ;
    END
  END plaintext[15]
  PIN plaintext[16]
    DIRECTION INPUT ;
    USE SIGNAL ;
    ANTENNAGATEAREA 0.213000 ;
    PORT
      LAYER met3 ;
        RECT 1118.960 695.000 1119.560 695.600 ;
    END
  END plaintext[16]
  PIN plaintext[17]
    DIRECTION INPUT ;
    USE SIGNAL ;
    ANTENNAGATEAREA 0.213000 ;
    PORT
      LAYER met3 ;
        RECT 1118.960 707.240 1119.560 707.840 ;
    END
  END plaintext[17]
  PIN plaintext[18]
    DIRECTION INPUT ;
    USE SIGNAL ;
    ANTENNAGATEAREA 0.213000 ;
    PORT
      LAYER met3 ;
        RECT 1118.960 709.960 1119.560 710.560 ;
    END
  END plaintext[18]
  PIN plaintext[19]
    DIRECTION INPUT ;
    USE SIGNAL ;
    ANTENNAGATEAREA 0.213000 ;
    PORT
      LAYER met3 ;
        RECT 1118.960 635.160 1119.560 635.760 ;
    END
  END plaintext[19]
  PIN plaintext[1]
    DIRECTION INPUT ;
    USE SIGNAL ;
    ANTENNAGATEAREA 0.213000 ;
    PORT
      LAYER met3 ;
        RECT 1118.960 714.040 1119.560 714.640 ;
    END
  END plaintext[1]
  PIN plaintext[20]
    DIRECTION INPUT ;
    USE SIGNAL ;
    ANTENNAGATEAREA 0.213000 ;
    PORT
      LAYER met3 ;
        RECT 1118.960 703.160 1119.560 703.760 ;
    END
  END plaintext[20]
  PIN plaintext[21]
    DIRECTION INPUT ;
    USE SIGNAL ;
    ANTENNAGATEAREA 0.213000 ;
    PORT
      LAYER met3 ;
        RECT 1118.960 641.960 1119.560 642.560 ;
    END
  END plaintext[21]
  PIN plaintext[22]
    DIRECTION INPUT ;
    USE SIGNAL ;
    ANTENNAGATEAREA 0.213000 ;
    PORT
      LAYER met3 ;
        RECT 1118.960 705.880 1119.560 706.480 ;
    END
  END plaintext[22]
  PIN plaintext[23]
    DIRECTION INPUT ;
    USE SIGNAL ;
    ANTENNAGATEAREA 0.213000 ;
    PORT
      LAYER met3 ;
        RECT 1118.960 704.520 1119.560 705.120 ;
    END
  END plaintext[23]
  PIN plaintext[24]
    DIRECTION INPUT ;
    USE SIGNAL ;
    ANTENNAGATEAREA 0.196500 ;
    PORT
      LAYER met3 ;
        RECT 1118.960 739.880 1119.560 740.480 ;
    END
  END plaintext[24]
  PIN plaintext[25]
    DIRECTION INPUT ;
    USE SIGNAL ;
    ANTENNAGATEAREA 0.196500 ;
    PORT
      LAYER met3 ;
        RECT 1118.960 708.600 1119.560 709.200 ;
    END
  END plaintext[25]
  PIN plaintext[26]
    DIRECTION INPUT ;
    USE SIGNAL ;
    ANTENNAGATEAREA 0.196500 ;
    PORT
      LAYER met3 ;
        RECT 1118.960 701.800 1119.560 702.400 ;
    END
  END plaintext[26]
  PIN plaintext[27]
    DIRECTION INPUT ;
    USE SIGNAL ;
    ANTENNAGATEAREA 0.196500 ;
    PORT
      LAYER met3 ;
        RECT 1118.960 696.360 1119.560 696.960 ;
    END
  END plaintext[27]
  PIN plaintext[28]
    DIRECTION INPUT ;
    USE SIGNAL ;
    ANTENNAGATEAREA 0.196500 ;
    PORT
      LAYER met3 ;
        RECT 1118.960 686.840 1119.560 687.440 ;
    END
  END plaintext[28]
  PIN plaintext[29]
    DIRECTION INPUT ;
    USE SIGNAL ;
    ANTENNAGATEAREA 0.196500 ;
    PORT
      LAYER met2 ;
        RECT 759.090 1130.000 759.370 1130.280 ;
    END
  END plaintext[29]
  PIN plaintext[2]
    DIRECTION INPUT ;
    USE SIGNAL ;
    ANTENNAGATEAREA 0.213000 ;
    PORT
      LAYER met3 ;
        RECT 1118.960 730.360 1119.560 730.960 ;
    END
  END plaintext[2]
  PIN plaintext[30]
    DIRECTION INPUT ;
    USE SIGNAL ;
    ANTENNAGATEAREA 0.196500 ;
    PORT
      LAYER met3 ;
        RECT 1118.960 692.280 1119.560 692.880 ;
    END
  END plaintext[30]
  PIN plaintext[31]
    DIRECTION INPUT ;
    USE SIGNAL ;
    ANTENNAGATEAREA 0.196500 ;
    PORT
      LAYER met3 ;
        RECT 1118.960 690.920 1119.560 691.520 ;
    END
  END plaintext[31]
  PIN plaintext[32]
    DIRECTION INPUT ;
    USE SIGNAL ;
    ANTENNAGATEAREA 0.213000 ;
    PORT
      LAYER met3 ;
        RECT 0.000 319.640 0.600 320.240 ;
    END
  END plaintext[32]
  PIN plaintext[33]
    DIRECTION INPUT ;
    USE SIGNAL ;
    ANTENNAGATEAREA 0.213000 ;
    PORT
      LAYER met3 ;
        RECT 0.000 394.440 0.600 395.040 ;
    END
  END plaintext[33]
  PIN plaintext[34]
    DIRECTION INPUT ;
    USE SIGNAL ;
    ANTENNAGATEAREA 0.213000 ;
    PORT
      LAYER met3 ;
        RECT 0.000 390.360 0.600 390.960 ;
    END
  END plaintext[34]
  PIN plaintext[35]
    DIRECTION INPUT ;
    USE SIGNAL ;
    ANTENNAGATEAREA 0.213000 ;
    PORT
      LAYER met3 ;
        RECT 0.000 398.520 0.600 399.120 ;
    END
  END plaintext[35]
  PIN plaintext[36]
    DIRECTION INPUT ;
    USE SIGNAL ;
    ANTENNAGATEAREA 0.213000 ;
    PORT
      LAYER met3 ;
        RECT 0.000 397.160 0.600 397.760 ;
    END
  END plaintext[36]
  PIN plaintext[37]
    DIRECTION INPUT ;
    USE SIGNAL ;
    ANTENNAGATEAREA 0.213000 ;
    PORT
      LAYER met3 ;
        RECT 0.000 395.800 0.600 396.400 ;
    END
  END plaintext[37]
  PIN plaintext[38]
    DIRECTION INPUT ;
    USE SIGNAL ;
    ANTENNAGATEAREA 0.213000 ;
    PORT
      LAYER met3 ;
        RECT 0.000 334.600 0.600 335.200 ;
    END
  END plaintext[38]
  PIN plaintext[39]
    DIRECTION INPUT ;
    USE SIGNAL ;
    ANTENNAGATEAREA 0.213000 ;
    PORT
      LAYER met3 ;
        RECT 0.000 315.560 0.600 316.160 ;
    END
  END plaintext[39]
  PIN plaintext[3]
    DIRECTION INPUT ;
    USE SIGNAL ;
    ANTENNAGATEAREA 0.213000 ;
    PORT
      LAYER met3 ;
        RECT 1118.960 719.480 1119.560 720.080 ;
    END
  END plaintext[3]
  PIN plaintext[40]
    DIRECTION INPUT ;
    USE SIGNAL ;
    ANTENNAGATEAREA 0.159000 ;
    PORT
      LAYER met2 ;
        RECT 286.210 0.000 286.490 0.280 ;
    END
  END plaintext[40]
  PIN plaintext[41]
    DIRECTION INPUT ;
    USE SIGNAL ;
    ANTENNAGATEAREA 0.159000 ;
    PORT
      LAYER met2 ;
        RECT 284.370 0.000 284.650 0.280 ;
    END
  END plaintext[41]
  PIN plaintext[42]
    DIRECTION INPUT ;
    USE SIGNAL ;
    ANTENNAGATEAREA 0.159000 ;
    PORT
      LAYER met2 ;
        RECT 287.130 0.000 287.410 0.280 ;
    END
  END plaintext[42]
  PIN plaintext[43]
    DIRECTION INPUT ;
    USE SIGNAL ;
    ANTENNAGATEAREA 0.159000 ;
    PORT
      LAYER met2 ;
        RECT 289.890 0.000 290.170 0.280 ;
    END
  END plaintext[43]
  PIN plaintext[44]
    DIRECTION INPUT ;
    USE SIGNAL ;
    ANTENNAGATEAREA 0.159000 ;
    PORT
      LAYER met2 ;
        RECT 279.770 0.000 280.050 0.280 ;
    END
  END plaintext[44]
  PIN plaintext[45]
    DIRECTION INPUT ;
    USE SIGNAL ;
    ANTENNAGATEAREA 0.213000 ;
    PORT
      LAYER met3 ;
        RECT 0.000 254.360 0.600 254.960 ;
    END
  END plaintext[45]
  PIN plaintext[46]
    DIRECTION INPUT ;
    USE SIGNAL ;
    ANTENNAGATEAREA 0.213000 ;
    PORT
      LAYER met3 ;
        RECT 0.000 326.440 0.600 327.040 ;
    END
  END plaintext[46]
  PIN plaintext[47]
    DIRECTION INPUT ;
    USE SIGNAL ;
    ANTENNAGATEAREA 0.213000 ;
    PORT
      LAYER met3 ;
        RECT 0.000 259.800 0.600 260.400 ;
    END
  END plaintext[47]
  PIN plaintext[48]
    DIRECTION INPUT ;
    USE SIGNAL ;
    ANTENNAGATEAREA 0.213000 ;
    PORT
      LAYER met3 ;
        RECT 0.000 338.680 0.600 339.280 ;
    END
  END plaintext[48]
  PIN plaintext[49]
    DIRECTION INPUT ;
    USE SIGNAL ;
    ANTENNAGATEAREA 0.213000 ;
    PORT
      LAYER met3 ;
        RECT 0.000 391.720 0.600 392.320 ;
    END
  END plaintext[49]
  PIN plaintext[4]
    DIRECTION INPUT ;
    USE SIGNAL ;
    ANTENNAGATEAREA 0.213000 ;
    PORT
      LAYER met3 ;
        RECT 1118.960 726.280 1119.560 726.880 ;
    END
  END plaintext[4]
  PIN plaintext[50]
    DIRECTION INPUT ;
    USE SIGNAL ;
    ANTENNAGATEAREA 0.213000 ;
    PORT
      LAYER met3 ;
        RECT 0.000 349.560 0.600 350.160 ;
    END
  END plaintext[50]
  PIN plaintext[51]
    DIRECTION INPUT ;
    USE SIGNAL ;
    ANTENNAGATEAREA 0.213000 ;
    PORT
      LAYER met3 ;
        RECT 0.000 352.280 0.600 352.880 ;
    END
  END plaintext[51]
  PIN plaintext[52]
    DIRECTION INPUT ;
    USE SIGNAL ;
    ANTENNAGATEAREA 0.213000 ;
    PORT
      LAYER met3 ;
        RECT 0.000 345.480 0.600 346.080 ;
    END
  END plaintext[52]
  PIN plaintext[53]
    DIRECTION INPUT ;
    USE SIGNAL ;
    ANTENNAGATEAREA 0.213000 ;
    PORT
      LAYER met3 ;
        RECT 0.000 368.600 0.600 369.200 ;
    END
  END plaintext[53]
  PIN plaintext[54]
    DIRECTION INPUT ;
    USE SIGNAL ;
    ANTENNAGATEAREA 0.213000 ;
    PORT
      LAYER met3 ;
        RECT 0.000 360.440 0.600 361.040 ;
    END
  END plaintext[54]
  PIN plaintext[55]
    DIRECTION INPUT ;
    USE SIGNAL ;
    ANTENNAGATEAREA 0.213000 ;
    PORT
      LAYER met3 ;
        RECT 0.000 344.120 0.600 344.720 ;
    END
  END plaintext[55]
  PIN plaintext[56]
    DIRECTION INPUT ;
    USE SIGNAL ;
    ANTENNAGATEAREA 0.213000 ;
    PORT
      LAYER met3 ;
        RECT 0.000 314.200 0.600 314.800 ;
    END
  END plaintext[56]
  PIN plaintext[57]
    DIRECTION INPUT ;
    USE SIGNAL ;
    ANTENNAGATEAREA 0.213000 ;
    PORT
      LAYER met3 ;
        RECT 0.000 263.880 0.600 264.480 ;
    END
  END plaintext[57]
  PIN plaintext[58]
    DIRECTION INPUT ;
    USE SIGNAL ;
    ANTENNAGATEAREA 0.213000 ;
    PORT
      LAYER met3 ;
        RECT 0.000 236.680 0.600 237.280 ;
    END
  END plaintext[58]
  PIN plaintext[59]
    DIRECTION INPUT ;
    USE SIGNAL ;
    ANTENNAGATEAREA 0.213000 ;
    PORT
      LAYER met3 ;
        RECT 0.000 316.920 0.600 317.520 ;
    END
  END plaintext[59]
  PIN plaintext[5]
    DIRECTION INPUT ;
    USE SIGNAL ;
    ANTENNAGATEAREA 0.213000 ;
    PORT
      LAYER met3 ;
        RECT 1118.960 731.720 1119.560 732.320 ;
    END
  END plaintext[5]
  PIN plaintext[60]
    DIRECTION INPUT ;
    USE SIGNAL ;
    ANTENNAGATEAREA 0.213000 ;
    PORT
      LAYER met3 ;
        RECT 0.000 310.120 0.600 310.720 ;
    END
  END plaintext[60]
  PIN plaintext[61]
    DIRECTION INPUT ;
    USE SIGNAL ;
    ANTENNAGATEAREA 0.213000 ;
    PORT
      LAYER met3 ;
        RECT 0.000 303.320 0.600 303.920 ;
    END
  END plaintext[61]
  PIN plaintext[62]
    DIRECTION INPUT ;
    USE SIGNAL ;
    ANTENNAGATEAREA 0.213000 ;
    PORT
      LAYER met3 ;
        RECT 0.000 242.120 0.600 242.720 ;
    END
  END plaintext[62]
  PIN plaintext[63]
    DIRECTION INPUT ;
    USE SIGNAL ;
    ANTENNAGATEAREA 0.213000 ;
    PORT
      LAYER met3 ;
        RECT 0.000 276.120 0.600 276.720 ;
    END
  END plaintext[63]
  PIN plaintext[64]
    DIRECTION INPUT ;
    USE SIGNAL ;
    ANTENNAGATEAREA 0.213000 ;
    PORT
      LAYER met2 ;
        RECT 439.850 1130.000 440.130 1130.280 ;
    END
  END plaintext[64]
  PIN plaintext[65]
    DIRECTION INPUT ;
    USE SIGNAL ;
    ANTENNAGATEAREA 0.213000 ;
    PORT
      LAYER met2 ;
        RECT 447.210 1130.000 447.490 1130.280 ;
    END
  END plaintext[65]
  PIN plaintext[66]
    DIRECTION INPUT ;
    USE SIGNAL ;
    ANTENNAGATEAREA 0.213000 ;
    PORT
      LAYER met2 ;
        RECT 443.530 1130.000 443.810 1130.280 ;
    END
  END plaintext[66]
  PIN plaintext[67]
    DIRECTION INPUT ;
    USE SIGNAL ;
    ANTENNAGATEAREA 0.213000 ;
    PORT
      LAYER met2 ;
        RECT 444.450 1130.000 444.730 1130.280 ;
    END
  END plaintext[67]
  PIN plaintext[68]
    DIRECTION INPUT ;
    USE SIGNAL ;
    ANTENNAGATEAREA 0.213000 ;
    PORT
      LAYER met2 ;
        RECT 449.970 1130.000 450.250 1130.280 ;
    END
  END plaintext[68]
  PIN plaintext[69]
    DIRECTION INPUT ;
    USE SIGNAL ;
    ANTENNAGATEAREA 0.196500 ;
    PORT
      LAYER met2 ;
        RECT 469.290 1130.000 469.570 1130.280 ;
    END
  END plaintext[69]
  PIN plaintext[6]
    DIRECTION INPUT ;
    USE SIGNAL ;
    ANTENNAGATEAREA 0.213000 ;
    PORT
      LAYER met3 ;
        RECT 1118.960 733.080 1119.560 733.680 ;
    END
  END plaintext[6]
  PIN plaintext[70]
    DIRECTION INPUT ;
    USE SIGNAL ;
    ANTENNAGATEAREA 0.196500 ;
    PORT
      LAYER met2 ;
        RECT 461.930 1130.000 462.210 1130.280 ;
    END
  END plaintext[70]
  PIN plaintext[71]
    DIRECTION INPUT ;
    USE SIGNAL ;
    ANTENNAGATEAREA 0.196500 ;
    PORT
      LAYER met2 ;
        RECT 455.490 1130.000 455.770 1130.280 ;
    END
  END plaintext[71]
  PIN plaintext[72]
    DIRECTION INPUT ;
    USE SIGNAL ;
    ANTENNAGATEAREA 0.196500 ;
    PORT
      LAYER met2 ;
        RECT 409.490 1130.000 409.770 1130.280 ;
    END
  END plaintext[72]
  PIN plaintext[73]
    DIRECTION INPUT ;
    USE SIGNAL ;
    ANTENNAGATEAREA 0.196500 ;
    PORT
      LAYER met2 ;
        RECT 426.050 1130.000 426.330 1130.280 ;
    END
  END plaintext[73]
  PIN plaintext[74]
    DIRECTION INPUT ;
    USE SIGNAL ;
    ANTENNAGATEAREA 0.196500 ;
    PORT
      LAYER met2 ;
        RECT 403.970 1130.000 404.250 1130.280 ;
    END
  END plaintext[74]
  PIN plaintext[75]
    DIRECTION INPUT ;
    USE SIGNAL ;
    ANTENNAGATEAREA 0.196500 ;
    PORT
      LAYER met2 ;
        RECT 480.330 1130.000 480.610 1130.280 ;
    END
  END plaintext[75]
  PIN plaintext[76]
    DIRECTION INPUT ;
    USE SIGNAL ;
    ANTENNAGATEAREA 0.196500 ;
    PORT
      LAYER met2 ;
        RECT 404.890 1130.000 405.170 1130.280 ;
    END
  END plaintext[76]
  PIN plaintext[77]
    DIRECTION INPUT ;
    USE SIGNAL ;
    ANTENNAGATEAREA 0.196500 ;
    PORT
      LAYER met2 ;
        RECT 405.810 1130.000 406.090 1130.280 ;
    END
  END plaintext[77]
  PIN plaintext[78]
    DIRECTION INPUT ;
    USE SIGNAL ;
    ANTENNAGATEAREA 0.196500 ;
    PORT
      LAYER met2 ;
        RECT 423.290 1130.000 423.570 1130.280 ;
    END
  END plaintext[78]
  PIN plaintext[79]
    DIRECTION INPUT ;
    USE SIGNAL ;
    ANTENNAGATEAREA 0.196500 ;
    PORT
      LAYER met2 ;
        RECT 407.650 1130.000 407.930 1130.280 ;
    END
  END plaintext[79]
  PIN plaintext[7]
    DIRECTION INPUT ;
    USE SIGNAL ;
    ANTENNAGATEAREA 0.213000 ;
    PORT
      LAYER met3 ;
        RECT 1118.960 652.840 1119.560 653.440 ;
    END
  END plaintext[7]
  PIN plaintext[80]
    DIRECTION INPUT ;
    USE SIGNAL ;
    ANTENNAGATEAREA 0.213000 ;
    PORT
      LAYER met3 ;
        RECT 0.000 731.720 0.600 732.320 ;
    END
  END plaintext[80]
  PIN plaintext[81]
    DIRECTION INPUT ;
    USE SIGNAL ;
    ANTENNAGATEAREA 0.213000 ;
    PORT
      LAYER met3 ;
        RECT 0.000 738.520 0.600 739.120 ;
    END
  END plaintext[81]
  PIN plaintext[82]
    DIRECTION INPUT ;
    USE SIGNAL ;
    ANTENNAGATEAREA 0.213000 ;
    PORT
      LAYER met3 ;
        RECT 0.000 763.000 0.600 763.600 ;
    END
  END plaintext[82]
  PIN plaintext[83]
    DIRECTION INPUT ;
    USE SIGNAL ;
    ANTENNAGATEAREA 0.213000 ;
    PORT
      LAYER met3 ;
        RECT 0.000 746.680 0.600 747.280 ;
    END
  END plaintext[83]
  PIN plaintext[84]
    DIRECTION INPUT ;
    USE SIGNAL ;
    ANTENNAGATEAREA 0.213000 ;
    PORT
      LAYER met3 ;
        RECT 0.000 753.480 0.600 754.080 ;
    END
  END plaintext[84]
  PIN plaintext[85]
    DIRECTION INPUT ;
    USE SIGNAL ;
    ANTENNAGATEAREA 0.213000 ;
    PORT
      LAYER met3 ;
        RECT 0.000 765.720 0.600 766.320 ;
    END
  END plaintext[85]
  PIN plaintext[86]
    DIRECTION INPUT ;
    USE SIGNAL ;
    ANTENNAGATEAREA 0.213000 ;
    PORT
      LAYER met3 ;
        RECT 0.000 771.160 0.600 771.760 ;
    END
  END plaintext[86]
  PIN plaintext[87]
    DIRECTION INPUT ;
    USE SIGNAL ;
    ANTENNAGATEAREA 0.213000 ;
    PORT
      LAYER met3 ;
        RECT 0.000 772.520 0.600 773.120 ;
    END
  END plaintext[87]
  PIN plaintext[88]
    DIRECTION INPUT ;
    USE SIGNAL ;
    ANTENNAGATEAREA 0.196500 ;
    PORT
      LAYER met3 ;
        RECT 0.000 741.240 0.600 741.840 ;
    END
  END plaintext[88]
  PIN plaintext[89]
    DIRECTION INPUT ;
    USE SIGNAL ;
    ANTENNAGATEAREA 0.196500 ;
    PORT
      LAYER met3 ;
        RECT 0.000 757.560 0.600 758.160 ;
    END
  END plaintext[89]
  PIN plaintext[8]
    DIRECTION INPUT ;
    USE SIGNAL ;
    ANTENNAGATEAREA 0.196500 ;
    PORT
      LAYER met2 ;
        RECT 841.890 1130.000 842.170 1130.280 ;
    END
  END plaintext[8]
  PIN plaintext[90]
    DIRECTION INPUT ;
    USE SIGNAL ;
    ANTENNAGATEAREA 0.196500 ;
    PORT
      LAYER met3 ;
        RECT 0.000 750.760 0.600 751.360 ;
    END
  END plaintext[90]
  PIN plaintext[91]
    DIRECTION INPUT ;
    USE SIGNAL ;
    ANTENNAGATEAREA 0.196500 ;
    PORT
      LAYER met3 ;
        RECT 0.000 764.360 0.600 764.960 ;
    END
  END plaintext[91]
  PIN plaintext[92]
    DIRECTION INPUT ;
    USE SIGNAL ;
    ANTENNAGATEAREA 0.196500 ;
    PORT
      LAYER met3 ;
        RECT 0.000 767.080 0.600 767.680 ;
    END
  END plaintext[92]
  PIN plaintext[93]
    DIRECTION INPUT ;
    USE SIGNAL ;
    ANTENNAGATEAREA 0.196500 ;
    PORT
      LAYER met2 ;
        RECT 408.570 1130.000 408.850 1130.280 ;
    END
  END plaintext[93]
  PIN plaintext[94]
    DIRECTION INPUT ;
    USE SIGNAL ;
    ANTENNAGATEAREA 0.196500 ;
    PORT
      LAYER met2 ;
        RECT 415.930 1130.000 416.210 1130.280 ;
    END
  END plaintext[94]
  PIN plaintext[95]
    DIRECTION INPUT ;
    USE SIGNAL ;
    ANTENNAGATEAREA 0.196500 ;
    PORT
      LAYER met2 ;
        RECT 401.210 1130.000 401.490 1130.280 ;
    END
  END plaintext[95]
  PIN plaintext[96]
    DIRECTION INPUT ;
    USE SIGNAL ;
    ANTENNAGATEAREA 0.159000 ;
    PORT
      LAYER met2 ;
        RECT 290.810 0.000 291.090 0.280 ;
    END
  END plaintext[96]
  PIN plaintext[97]
    DIRECTION INPUT ;
    USE SIGNAL ;
    ANTENNAGATEAREA 0.196500 ;
    PORT
      LAYER met3 ;
        RECT 0.000 341.400 0.600 342.000 ;
    END
  END plaintext[97]
  PIN plaintext[98]
    DIRECTION INPUT ;
    USE SIGNAL ;
    ANTENNAGATEAREA 0.159000 ;
    PORT
      LAYER met2 ;
        RECT 303.690 0.000 303.970 0.280 ;
    END
  END plaintext[98]
  PIN plaintext[99]
    DIRECTION INPUT ;
    USE SIGNAL ;
    ANTENNAGATEAREA 0.159000 ;
    PORT
      LAYER met2 ;
        RECT 273.330 0.000 273.610 0.280 ;
    END
  END plaintext[99]
  PIN plaintext[9]
    DIRECTION INPUT ;
    USE SIGNAL ;
    ANTENNAGATEAREA 0.196500 ;
    PORT
      LAYER met2 ;
        RECT 846.490 1130.000 846.770 1130.280 ;
    END
  END plaintext[9]
  PIN rst
    DIRECTION INPUT ;
    USE SIGNAL ;
    ANTENNAGATEAREA 0.213000 ;
    PORT
      LAYER met3 ;
        RECT 1118.960 225.800 1119.560 226.400 ;
    END
  END rst
  PIN start
    DIRECTION INPUT ;
    USE SIGNAL ;
    ANTENNAGATEAREA 0.213000 ;
    PORT
      LAYER met3 ;
        RECT 1118.960 229.880 1119.560 230.480 ;
    END
  END start
  OBS
      LAYER nwell ;
        RECT 5.330 10.795 1113.850 1118.110 ;
      LAYER li1 ;
        RECT 5.520 10.795 1113.660 1118.005 ;
      LAYER met1 ;
        RECT 0.070 0.720 1119.110 1130.120 ;
      LAYER met2 ;
        RECT 0.090 1129.720 380.690 1130.210 ;
        RECT 381.530 1129.720 400.930 1130.210 ;
        RECT 401.770 1129.720 403.690 1130.210 ;
        RECT 404.530 1129.720 404.610 1130.210 ;
        RECT 405.450 1129.720 405.530 1130.210 ;
        RECT 406.370 1129.720 407.370 1130.210 ;
        RECT 408.210 1129.720 408.290 1130.210 ;
        RECT 409.130 1129.720 409.210 1130.210 ;
        RECT 410.050 1129.720 415.650 1130.210 ;
        RECT 416.490 1129.720 423.010 1130.210 ;
        RECT 423.850 1129.720 425.770 1130.210 ;
        RECT 426.610 1129.720 439.570 1130.210 ;
        RECT 440.410 1129.720 443.250 1130.210 ;
        RECT 444.090 1129.720 444.170 1130.210 ;
        RECT 445.010 1129.720 446.930 1130.210 ;
        RECT 447.770 1129.720 449.690 1130.210 ;
        RECT 450.530 1129.720 455.210 1130.210 ;
        RECT 456.050 1129.720 461.650 1130.210 ;
        RECT 462.490 1129.720 469.010 1130.210 ;
        RECT 469.850 1129.720 479.130 1130.210 ;
        RECT 479.970 1129.720 480.050 1130.210 ;
        RECT 480.890 1129.720 539.850 1130.210 ;
        RECT 540.690 1129.720 540.770 1130.210 ;
        RECT 541.610 1129.720 541.690 1130.210 ;
        RECT 542.530 1129.720 542.610 1130.210 ;
        RECT 543.450 1129.720 543.530 1130.210 ;
        RECT 544.370 1129.720 544.450 1130.210 ;
        RECT 545.290 1129.720 545.370 1130.210 ;
        RECT 546.210 1129.720 546.290 1130.210 ;
        RECT 547.130 1129.720 547.210 1130.210 ;
        RECT 548.050 1129.720 548.130 1130.210 ;
        RECT 548.970 1129.720 549.050 1130.210 ;
        RECT 549.890 1129.720 549.970 1130.210 ;
        RECT 550.810 1129.720 550.890 1130.210 ;
        RECT 551.730 1129.720 551.810 1130.210 ;
        RECT 552.650 1129.720 552.730 1130.210 ;
        RECT 553.570 1129.720 553.650 1130.210 ;
        RECT 554.490 1129.720 554.570 1130.210 ;
        RECT 555.410 1129.720 555.490 1130.210 ;
        RECT 556.330 1129.720 556.410 1130.210 ;
        RECT 557.250 1129.720 557.330 1130.210 ;
        RECT 558.170 1129.720 558.250 1130.210 ;
        RECT 559.090 1129.720 559.170 1130.210 ;
        RECT 560.010 1129.720 560.090 1130.210 ;
        RECT 560.930 1129.720 561.010 1130.210 ;
        RECT 561.850 1129.720 561.930 1130.210 ;
        RECT 562.770 1129.720 562.850 1130.210 ;
        RECT 563.690 1129.720 563.770 1130.210 ;
        RECT 564.610 1129.720 564.690 1130.210 ;
        RECT 565.530 1129.720 571.130 1130.210 ;
        RECT 571.970 1129.720 573.890 1130.210 ;
        RECT 574.730 1129.720 575.730 1130.210 ;
        RECT 576.570 1129.720 576.650 1130.210 ;
        RECT 577.490 1129.720 580.330 1130.210 ;
        RECT 581.170 1129.720 581.250 1130.210 ;
        RECT 582.090 1129.720 584.010 1130.210 ;
        RECT 584.850 1129.720 584.930 1130.210 ;
        RECT 585.770 1129.720 586.770 1130.210 ;
        RECT 587.610 1129.720 592.290 1130.210 ;
        RECT 593.130 1129.720 594.130 1130.210 ;
        RECT 594.970 1129.720 595.050 1130.210 ;
        RECT 595.890 1129.720 595.970 1130.210 ;
        RECT 596.810 1129.720 605.170 1130.210 ;
        RECT 606.010 1129.720 606.090 1130.210 ;
        RECT 606.930 1129.720 607.010 1130.210 ;
        RECT 607.850 1129.720 607.930 1130.210 ;
        RECT 608.770 1129.720 608.850 1130.210 ;
        RECT 609.690 1129.720 616.210 1130.210 ;
        RECT 617.050 1129.720 618.050 1130.210 ;
        RECT 618.890 1129.720 618.970 1130.210 ;
        RECT 619.810 1129.720 627.250 1130.210 ;
        RECT 628.090 1129.720 628.170 1130.210 ;
        RECT 629.010 1129.720 629.090 1130.210 ;
        RECT 629.930 1129.720 630.010 1130.210 ;
        RECT 630.850 1129.720 632.770 1130.210 ;
        RECT 633.610 1129.720 639.210 1130.210 ;
        RECT 640.050 1129.720 640.130 1130.210 ;
        RECT 640.970 1129.720 641.970 1130.210 ;
        RECT 642.810 1129.720 645.650 1130.210 ;
        RECT 646.490 1129.720 646.570 1130.210 ;
        RECT 647.410 1129.720 653.010 1130.210 ;
        RECT 653.850 1129.720 758.810 1130.210 ;
        RECT 759.650 1129.720 828.730 1130.210 ;
        RECT 829.570 1129.720 836.090 1130.210 ;
        RECT 836.930 1129.720 841.610 1130.210 ;
        RECT 842.450 1129.720 842.530 1130.210 ;
        RECT 843.370 1129.720 846.210 1130.210 ;
        RECT 847.050 1129.720 847.130 1130.210 ;
        RECT 847.970 1129.720 930.850 1130.210 ;
        RECT 931.690 1129.720 931.770 1130.210 ;
        RECT 932.610 1129.720 932.690 1130.210 ;
        RECT 933.530 1129.720 990.650 1130.210 ;
        RECT 991.490 1129.720 994.330 1130.210 ;
        RECT 995.170 1129.720 995.250 1130.210 ;
        RECT 996.090 1129.720 998.930 1130.210 ;
        RECT 999.770 1129.720 1000.770 1130.210 ;
        RECT 1001.610 1129.720 1005.370 1130.210 ;
        RECT 1006.210 1129.720 1013.650 1130.210 ;
        RECT 1014.490 1129.720 1014.570 1130.210 ;
        RECT 1015.410 1129.720 1016.410 1130.210 ;
        RECT 1017.250 1129.720 1018.250 1130.210 ;
        RECT 1019.090 1129.720 1019.170 1130.210 ;
        RECT 1020.010 1129.720 1025.610 1130.210 ;
        RECT 1026.450 1129.720 1026.530 1130.210 ;
        RECT 1027.370 1129.720 1031.130 1130.210 ;
        RECT 1031.970 1129.720 1119.090 1130.210 ;
        RECT 0.090 0.560 1119.090 1129.720 ;
        RECT 0.090 0.070 89.050 0.560 ;
        RECT 89.890 0.070 89.970 0.560 ;
        RECT 90.810 0.070 185.650 0.560 ;
        RECT 186.490 0.070 186.570 0.560 ;
        RECT 187.410 0.070 187.490 0.560 ;
        RECT 188.330 0.070 188.410 0.560 ;
        RECT 189.250 0.070 189.330 0.560 ;
        RECT 190.170 0.070 190.250 0.560 ;
        RECT 191.090 0.070 191.170 0.560 ;
        RECT 192.010 0.070 192.090 0.560 ;
        RECT 192.930 0.070 193.010 0.560 ;
        RECT 193.850 0.070 193.930 0.560 ;
        RECT 194.770 0.070 194.850 0.560 ;
        RECT 195.690 0.070 195.770 0.560 ;
        RECT 196.610 0.070 196.690 0.560 ;
        RECT 197.530 0.070 197.610 0.560 ;
        RECT 198.450 0.070 198.530 0.560 ;
        RECT 199.370 0.070 199.450 0.560 ;
        RECT 200.290 0.070 200.370 0.560 ;
        RECT 201.210 0.070 201.290 0.560 ;
        RECT 202.130 0.070 202.210 0.560 ;
        RECT 203.050 0.070 203.130 0.560 ;
        RECT 203.970 0.070 210.490 0.560 ;
        RECT 211.330 0.070 211.410 0.560 ;
        RECT 212.250 0.070 215.090 0.560 ;
        RECT 215.930 0.070 216.930 0.560 ;
        RECT 217.770 0.070 221.530 0.560 ;
        RECT 222.370 0.070 226.130 0.560 ;
        RECT 226.970 0.070 230.730 0.560 ;
        RECT 231.570 0.070 272.130 0.560 ;
        RECT 272.970 0.070 273.050 0.560 ;
        RECT 273.890 0.070 279.490 0.560 ;
        RECT 280.330 0.070 284.090 0.560 ;
        RECT 284.930 0.070 285.930 0.560 ;
        RECT 286.770 0.070 286.850 0.560 ;
        RECT 287.690 0.070 289.610 0.560 ;
        RECT 290.450 0.070 290.530 0.560 ;
        RECT 291.370 0.070 296.970 0.560 ;
        RECT 297.810 0.070 303.410 0.560 ;
        RECT 304.250 0.070 369.650 0.560 ;
        RECT 370.490 0.070 370.570 0.560 ;
        RECT 371.410 0.070 543.530 0.560 ;
        RECT 544.370 0.070 555.490 0.560 ;
        RECT 556.330 0.070 559.170 0.560 ;
        RECT 560.010 0.070 561.930 0.560 ;
        RECT 562.770 0.070 563.770 0.560 ;
        RECT 564.610 0.070 571.130 0.560 ;
        RECT 571.970 0.070 572.050 0.560 ;
        RECT 572.890 0.070 574.810 0.560 ;
        RECT 575.650 0.070 575.730 0.560 ;
        RECT 576.570 0.070 579.410 0.560 ;
        RECT 580.250 0.070 582.170 0.560 ;
        RECT 583.010 0.070 584.010 0.560 ;
        RECT 584.850 0.070 584.930 0.560 ;
        RECT 585.770 0.070 587.690 0.560 ;
        RECT 588.530 0.070 588.610 0.560 ;
        RECT 589.450 0.070 594.130 0.560 ;
        RECT 594.970 0.070 595.050 0.560 ;
        RECT 595.890 0.070 595.970 0.560 ;
        RECT 596.810 0.070 596.890 0.560 ;
        RECT 597.730 0.070 599.650 0.560 ;
        RECT 600.490 0.070 600.570 0.560 ;
        RECT 601.410 0.070 601.490 0.560 ;
        RECT 602.330 0.070 607.930 0.560 ;
        RECT 608.770 0.070 608.850 0.560 ;
        RECT 609.690 0.070 609.770 0.560 ;
        RECT 610.610 0.070 610.690 0.560 ;
        RECT 611.530 0.070 612.530 0.560 ;
        RECT 613.370 0.070 615.290 0.560 ;
        RECT 616.130 0.070 616.210 0.560 ;
        RECT 617.050 0.070 617.130 0.560 ;
        RECT 617.970 0.070 619.890 0.560 ;
        RECT 620.730 0.070 621.730 0.560 ;
        RECT 622.570 0.070 1119.090 0.560 ;
      LAYER met3 ;
        RECT 0.065 1019.680 1118.960 1123.185 ;
        RECT 1.000 1018.280 1118.960 1019.680 ;
        RECT 0.065 1016.960 1118.960 1018.280 ;
        RECT 1.000 1015.560 1118.960 1016.960 ;
        RECT 0.065 997.920 1118.960 1015.560 ;
        RECT 0.065 996.520 1118.560 997.920 ;
        RECT 0.065 991.120 1118.960 996.520 ;
        RECT 0.065 985.640 1118.560 991.120 ;
        RECT 0.065 982.960 1118.960 985.640 ;
        RECT 0.065 981.560 1118.560 982.960 ;
        RECT 0.065 980.240 1118.960 981.560 ;
        RECT 0.065 976.120 1118.560 980.240 ;
        RECT 0.065 973.440 1118.960 976.120 ;
        RECT 0.065 970.680 1118.560 973.440 ;
        RECT 0.065 969.360 1118.960 970.680 ;
        RECT 0.065 967.960 1118.560 969.360 ;
        RECT 0.065 965.280 1118.960 967.960 ;
        RECT 0.065 963.880 1118.560 965.280 ;
        RECT 0.065 962.560 1118.960 963.880 ;
        RECT 0.065 955.720 1118.560 962.560 ;
        RECT 0.065 773.520 1118.960 955.720 ;
        RECT 1.000 770.760 1118.960 773.520 ;
        RECT 0.065 768.080 1118.960 770.760 ;
        RECT 1.000 762.600 1118.960 768.080 ;
        RECT 0.065 758.560 1118.960 762.600 ;
        RECT 1.000 757.160 1118.960 758.560 ;
        RECT 0.065 754.480 1118.960 757.160 ;
        RECT 1.000 753.080 1118.960 754.480 ;
        RECT 0.065 751.760 1118.960 753.080 ;
        RECT 1.000 750.360 1118.960 751.760 ;
        RECT 0.065 747.680 1118.960 750.360 ;
        RECT 1.000 746.280 1118.960 747.680 ;
        RECT 0.065 742.240 1118.960 746.280 ;
        RECT 1.000 740.880 1118.960 742.240 ;
        RECT 1.000 740.840 1118.560 740.880 ;
        RECT 0.065 739.520 1118.560 740.840 ;
        RECT 1.000 738.120 1118.560 739.520 ;
        RECT 0.065 736.760 1118.560 738.120 ;
        RECT 0.065 734.080 1118.960 736.760 ;
        RECT 0.065 732.720 1118.560 734.080 ;
        RECT 1.000 731.320 1118.560 732.720 ;
        RECT 0.065 729.960 1118.560 731.320 ;
        RECT 0.065 727.280 1118.960 729.960 ;
        RECT 0.065 725.880 1118.560 727.280 ;
        RECT 0.065 723.200 1118.960 725.880 ;
        RECT 0.065 721.800 1118.560 723.200 ;
        RECT 0.065 720.480 1118.960 721.800 ;
        RECT 0.065 719.080 1118.560 720.480 ;
        RECT 0.065 715.040 1118.960 719.080 ;
        RECT 0.065 713.640 1118.560 715.040 ;
        RECT 0.065 710.960 1118.960 713.640 ;
        RECT 0.065 701.400 1118.560 710.960 ;
        RECT 0.065 697.360 1118.960 701.400 ;
        RECT 0.065 694.600 1118.560 697.360 ;
        RECT 0.065 693.280 1118.960 694.600 ;
        RECT 0.065 690.520 1118.560 693.280 ;
        RECT 0.065 687.840 1118.960 690.520 ;
        RECT 0.065 686.440 1118.560 687.840 ;
        RECT 0.065 653.840 1118.960 686.440 ;
        RECT 0.065 652.440 1118.560 653.840 ;
        RECT 0.065 642.960 1118.960 652.440 ;
        RECT 0.065 641.560 1118.560 642.960 ;
        RECT 0.065 636.160 1118.960 641.560 ;
        RECT 0.065 634.760 1118.560 636.160 ;
        RECT 0.065 584.480 1118.960 634.760 ;
        RECT 1.000 568.160 1118.960 584.480 ;
        RECT 1.000 566.760 1118.560 568.160 ;
        RECT 0.065 560.000 1118.560 566.760 ;
        RECT 1.000 558.600 1118.560 560.000 ;
        RECT 0.065 545.000 1118.560 558.600 ;
        RECT 0.065 492.000 1118.960 545.000 ;
        RECT 1.000 490.600 1118.960 492.000 ;
        RECT 0.065 470.240 1118.960 490.600 ;
        RECT 1.000 468.840 1118.960 470.240 ;
        RECT 0.065 445.760 1118.960 468.840 ;
        RECT 1.000 444.360 1118.960 445.760 ;
        RECT 0.065 437.600 1118.960 444.360 ;
        RECT 1.000 436.200 1118.960 437.600 ;
        RECT 0.065 432.160 1118.960 436.200 ;
        RECT 1.000 418.520 1118.960 432.160 ;
        RECT 0.065 415.840 1118.960 418.520 ;
        RECT 1.000 411.720 1118.960 415.840 ;
        RECT 0.065 406.320 1118.960 411.720 ;
        RECT 1.000 403.560 1118.560 406.320 ;
        RECT 1.000 402.240 1118.960 403.560 ;
        RECT 1.000 400.840 1118.560 402.240 ;
        RECT 0.065 399.520 1118.960 400.840 ;
        RECT 1.000 395.440 1118.960 399.520 ;
        RECT 1.000 394.040 1118.560 395.440 ;
        RECT 0.065 392.720 1118.560 394.040 ;
        RECT 1.000 392.680 1118.560 392.720 ;
        RECT 1.000 389.960 1118.960 392.680 ;
        RECT 0.065 388.640 1118.960 389.960 ;
        RECT 0.065 385.880 1118.560 388.640 ;
        RECT 0.065 384.560 1118.960 385.880 ;
        RECT 0.065 383.160 1118.560 384.560 ;
        RECT 0.065 379.120 1118.960 383.160 ;
        RECT 0.065 376.360 1118.560 379.120 ;
        RECT 0.065 375.040 1118.960 376.360 ;
        RECT 0.065 373.640 1118.560 375.040 ;
        RECT 0.065 370.960 1118.960 373.640 ;
        RECT 0.065 369.600 1118.560 370.960 ;
        RECT 1.000 369.560 1118.560 369.600 ;
        RECT 1.000 368.200 1118.960 369.560 ;
        RECT 0.065 361.440 1118.960 368.200 ;
        RECT 1.000 360.040 1118.960 361.440 ;
        RECT 0.065 353.280 1118.960 360.040 ;
        RECT 1.000 351.880 1118.960 353.280 ;
        RECT 0.065 350.560 1118.960 351.880 ;
        RECT 1.000 349.160 1118.960 350.560 ;
        RECT 0.065 347.840 1118.960 349.160 ;
        RECT 1.000 332.840 1118.960 347.840 ;
        RECT 0.065 327.440 1118.960 332.840 ;
        RECT 1.000 326.040 1118.960 327.440 ;
        RECT 0.065 320.640 1118.960 326.040 ;
        RECT 1.000 319.240 1118.960 320.640 ;
        RECT 0.065 317.920 1118.960 319.240 ;
        RECT 1.000 313.840 1118.960 317.920 ;
        RECT 1.000 313.800 1118.560 313.840 ;
        RECT 0.065 312.480 1118.560 313.800 ;
        RECT 1.000 304.280 1118.560 312.480 ;
        RECT 1.000 302.960 1118.960 304.280 ;
        RECT 1.000 300.200 1118.560 302.960 ;
        RECT 1.000 296.120 1118.960 300.200 ;
        RECT 0.065 281.200 1118.960 296.120 ;
        RECT 0.065 277.120 1118.560 281.200 ;
        RECT 1.000 275.720 1118.560 277.120 ;
        RECT 0.065 273.000 1118.560 275.720 ;
        RECT 0.065 264.880 1118.960 273.000 ;
        RECT 1.000 262.120 1118.960 264.880 ;
        RECT 0.065 260.800 1118.960 262.120 ;
        RECT 1.000 259.400 1118.960 260.800 ;
        RECT 0.065 255.360 1118.960 259.400 ;
        RECT 1.000 253.960 1118.960 255.360 ;
        RECT 0.065 245.840 1118.960 253.960 ;
        RECT 0.065 243.120 1118.560 245.840 ;
        RECT 1.000 241.720 1118.560 243.120 ;
        RECT 0.065 240.400 1118.960 241.720 ;
        RECT 0.065 237.680 1118.560 240.400 ;
        RECT 1.000 236.280 1118.560 237.680 ;
        RECT 0.065 224.040 1118.560 236.280 ;
        RECT 0.065 222.720 1118.960 224.040 ;
        RECT 0.065 218.600 1118.560 222.720 ;
        RECT 0.065 217.280 1118.960 218.600 ;
        RECT 0.065 205.000 1118.560 217.280 ;
        RECT 0.065 198.240 1118.960 205.000 ;
        RECT 0.065 196.840 1118.560 198.240 ;
        RECT 0.065 5.615 1118.960 196.840 ;
      LAYER met4 ;
        RECT 0.790 10.240 20.640 1117.745 ;
        RECT 23.040 10.240 23.940 1117.745 ;
        RECT 26.340 10.240 174.240 1117.745 ;
        RECT 176.640 10.240 177.540 1117.745 ;
        RECT 179.940 10.240 327.840 1117.745 ;
        RECT 330.240 10.240 331.140 1117.745 ;
        RECT 333.540 10.240 481.440 1117.745 ;
        RECT 483.840 10.240 484.740 1117.745 ;
        RECT 487.140 10.240 635.040 1117.745 ;
        RECT 637.440 10.240 638.340 1117.745 ;
        RECT 640.740 10.240 788.640 1117.745 ;
        RECT 791.040 10.240 791.940 1117.745 ;
        RECT 794.340 10.240 942.240 1117.745 ;
        RECT 944.640 10.240 945.540 1117.745 ;
        RECT 947.940 10.240 1095.840 1117.745 ;
        RECT 1098.240 10.240 1099.140 1117.745 ;
        RECT 1101.540 10.240 1111.985 1117.745 ;
        RECT 0.790 8.335 1111.985 10.240 ;
      LAYER met5 ;
        RECT 0.580 1105.490 1111.700 1110.900 ;
        RECT 0.580 1097.390 3.920 1105.490 ;
        RECT 0.580 952.310 1111.700 1097.390 ;
        RECT 0.580 944.210 3.920 952.310 ;
        RECT 0.580 799.130 1111.700 944.210 ;
        RECT 0.580 791.030 3.920 799.130 ;
        RECT 0.580 645.950 1111.700 791.030 ;
        RECT 0.580 637.850 3.920 645.950 ;
        RECT 0.580 492.770 1111.700 637.850 ;
        RECT 0.580 484.670 3.920 492.770 ;
        RECT 0.580 339.590 1111.700 484.670 ;
        RECT 0.580 331.490 3.920 339.590 ;
        RECT 0.580 186.410 1111.700 331.490 ;
        RECT 0.580 178.310 3.920 186.410 ;
        RECT 0.580 33.230 1111.700 178.310 ;
        RECT 0.580 25.130 3.920 33.230 ;
        RECT 0.580 14.500 1111.700 25.130 ;
  END
END aes_top
END LIBRARY

